VERSION 5.7 ;
  NOWIREEXTENSIONATPIN ON ;
  DIVIDERCHAR "/" ;
  BUSBITCHARS "[]" ;
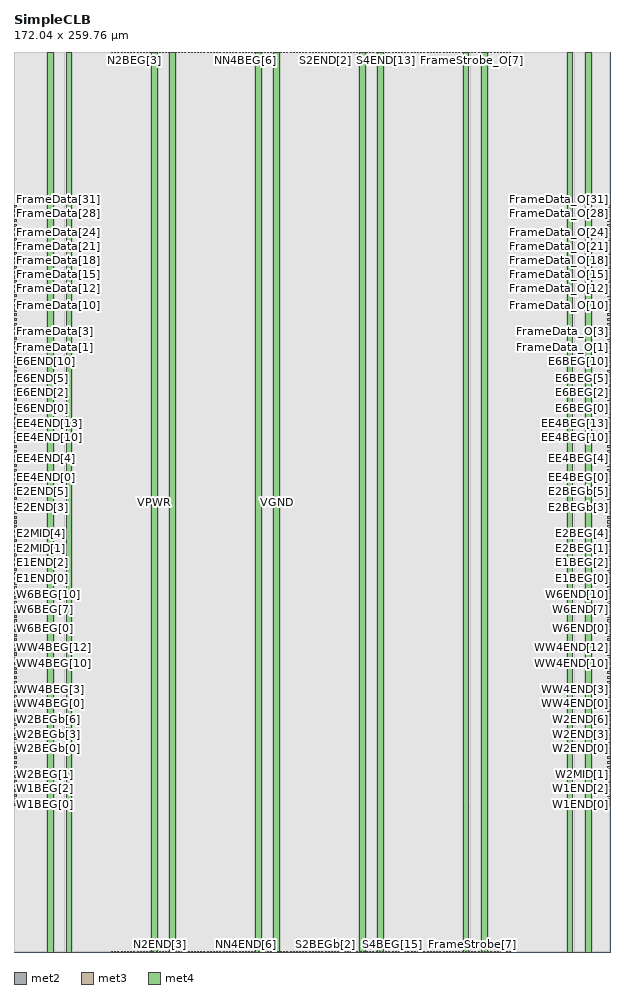
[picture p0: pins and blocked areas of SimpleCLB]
MACRO SimpleCLB
  CLASS BLOCK ;
  FOREIGN SimpleCLB ;
  ORIGIN 0.000 0.000 ;
  SIZE 172.040 BY 259.760 ;
  PIN Ci
    DIRECTION INPUT ;
    USE SIGNAL ;
    ANTENNAGATEAREA 1.485000 ;
    PORT
      LAYER met2 ;
        RECT 75.990 0.000 76.270 0.280 ;
    END
  END Ci
  PIN Co
    DIRECTION OUTPUT ;
    USE SIGNAL ;
    ANTENNADIFFAREA 1.782000 ;
    PORT
      LAYER met2 ;
        RECT 75.990 259.480 76.270 259.760 ;
    END
  END Co
  PIN E1BEG[0]
    DIRECTION OUTPUT ;
    USE SIGNAL ;
    ANTENNADIFFAREA 0.891000 ;
    PORT
      LAYER met3 ;
        RECT 171.440 107.480 172.040 108.080 ;
    END
  END E1BEG[0]
  PIN E1BEG[1]
    DIRECTION OUTPUT ;
    USE SIGNAL ;
    ANTENNADIFFAREA 0.891000 ;
    PORT
      LAYER met3 ;
        RECT 171.440 108.840 172.040 109.440 ;
    END
  END E1BEG[1]
  PIN E1BEG[2]
    DIRECTION OUTPUT ;
    USE SIGNAL ;
    ANTENNADIFFAREA 1.336500 ;
    PORT
      LAYER met3 ;
        RECT 171.440 110.200 172.040 110.800 ;
    END
  END E1BEG[2]
  PIN E1BEG[3]
    DIRECTION OUTPUT ;
    USE SIGNAL ;
    ANTENNADIFFAREA 0.891000 ;
    PORT
      LAYER met3 ;
        RECT 171.440 111.560 172.040 112.160 ;
    END
  END E1BEG[3]
  PIN E1END[0]
    DIRECTION INPUT ;
    USE SIGNAL ;
    ANTENNAGATEAREA 4.176900 ;
    ANTENNADIFFAREA 3.042900 ;
    PORT
      LAYER met3 ;
        RECT 0.000 107.480 0.600 108.080 ;
    END
  END E1END[0]
  PIN E1END[1]
    DIRECTION INPUT ;
    USE SIGNAL ;
    ANTENNAGATEAREA 1.134000 ;
    PORT
      LAYER met3 ;
        RECT 0.000 108.840 0.600 109.440 ;
    END
  END E1END[1]
  PIN E1END[2]
    DIRECTION INPUT ;
    USE SIGNAL ;
    ANTENNAGATEAREA 2.807100 ;
    ANTENNADIFFAREA 1.304100 ;
    PORT
      LAYER met3 ;
        RECT 0.000 110.200 0.600 110.800 ;
    END
  END E1END[2]
  PIN E1END[3]
    DIRECTION INPUT ;
    USE SIGNAL ;
    ANTENNAGATEAREA 0.339000 ;
    PORT
      LAYER met3 ;
        RECT 0.000 111.560 0.600 112.160 ;
    END
  END E1END[3]
  PIN E2BEG[0]
    DIRECTION OUTPUT ;
    USE SIGNAL ;
    ANTENNADIFFAREA 0.891000 ;
    PORT
      LAYER met3 ;
        RECT 171.440 112.920 172.040 113.520 ;
    END
  END E2BEG[0]
  PIN E2BEG[1]
    DIRECTION OUTPUT ;
    USE SIGNAL ;
    ANTENNADIFFAREA 0.891000 ;
    PORT
      LAYER met3 ;
        RECT 171.440 114.280 172.040 114.880 ;
    END
  END E2BEG[1]
  PIN E2BEG[2]
    DIRECTION OUTPUT ;
    USE SIGNAL ;
    ANTENNADIFFAREA 1.336500 ;
    PORT
      LAYER met3 ;
        RECT 171.440 115.640 172.040 116.240 ;
    END
  END E2BEG[2]
  PIN E2BEG[3]
    DIRECTION OUTPUT ;
    USE SIGNAL ;
    ANTENNADIFFAREA 1.336500 ;
    PORT
      LAYER met3 ;
        RECT 171.440 117.000 172.040 117.600 ;
    END
  END E2BEG[3]
  PIN E2BEG[4]
    DIRECTION OUTPUT ;
    USE SIGNAL ;
    ANTENNADIFFAREA 1.782000 ;
    PORT
      LAYER met3 ;
        RECT 171.440 118.360 172.040 118.960 ;
    END
  END E2BEG[4]
  PIN E2BEG[5]
    DIRECTION OUTPUT ;
    USE SIGNAL ;
    ANTENNADIFFAREA 1.336500 ;
    PORT
      LAYER met3 ;
        RECT 171.440 119.720 172.040 120.320 ;
    END
  END E2BEG[5]
  PIN E2BEG[6]
    DIRECTION OUTPUT ;
    USE SIGNAL ;
    ANTENNADIFFAREA 1.782000 ;
    PORT
      LAYER met3 ;
        RECT 171.440 121.080 172.040 121.680 ;
    END
  END E2BEG[6]
  PIN E2BEG[7]
    DIRECTION OUTPUT ;
    USE SIGNAL ;
    ANTENNADIFFAREA 1.336500 ;
    PORT
      LAYER met3 ;
        RECT 171.440 122.440 172.040 123.040 ;
    END
  END E2BEG[7]
  PIN E2BEGb[0]
    DIRECTION OUTPUT ;
    USE SIGNAL ;
    ANTENNADIFFAREA 0.445500 ;
    PORT
      LAYER met3 ;
        RECT 171.440 123.800 172.040 124.400 ;
    END
  END E2BEGb[0]
  PIN E2BEGb[1]
    DIRECTION OUTPUT ;
    USE SIGNAL ;
    ANTENNADIFFAREA 0.445500 ;
    PORT
      LAYER met3 ;
        RECT 171.440 125.160 172.040 125.760 ;
    END
  END E2BEGb[1]
  PIN E2BEGb[2]
    DIRECTION OUTPUT ;
    USE SIGNAL ;
    ANTENNADIFFAREA 0.445500 ;
    PORT
      LAYER met3 ;
        RECT 171.440 126.520 172.040 127.120 ;
    END
  END E2BEGb[2]
  PIN E2BEGb[3]
    DIRECTION OUTPUT ;
    USE SIGNAL ;
    ANTENNADIFFAREA 0.445500 ;
    PORT
      LAYER met3 ;
        RECT 171.440 127.880 172.040 128.480 ;
    END
  END E2BEGb[3]
  PIN E2BEGb[4]
    DIRECTION OUTPUT ;
    USE SIGNAL ;
    ANTENNADIFFAREA 0.445500 ;
    PORT
      LAYER met3 ;
        RECT 171.440 129.240 172.040 129.840 ;
    END
  END E2BEGb[4]
  PIN E2BEGb[5]
    DIRECTION OUTPUT ;
    USE SIGNAL ;
    ANTENNADIFFAREA 0.445500 ;
    PORT
      LAYER met3 ;
        RECT 171.440 130.600 172.040 131.200 ;
    END
  END E2BEGb[5]
  PIN E2BEGb[6]
    DIRECTION OUTPUT ;
    USE SIGNAL ;
    ANTENNADIFFAREA 0.445500 ;
    PORT
      LAYER met3 ;
        RECT 171.440 131.960 172.040 132.560 ;
    END
  END E2BEGb[6]
  PIN E2BEGb[7]
    DIRECTION OUTPUT ;
    USE SIGNAL ;
    ANTENNADIFFAREA 0.445500 ;
    PORT
      LAYER met3 ;
        RECT 171.440 133.320 172.040 133.920 ;
    END
  END E2BEGb[7]
  PIN E2END[0]
    DIRECTION INPUT ;
    USE SIGNAL ;
    ANTENNAGATEAREA 0.537000 ;
    PORT
      LAYER met3 ;
        RECT 0.000 123.800 0.600 124.400 ;
    END
  END E2END[0]
  PIN E2END[1]
    DIRECTION INPUT ;
    USE SIGNAL ;
    ANTENNAGATEAREA 0.537000 ;
    PORT
      LAYER met3 ;
        RECT 0.000 125.160 0.600 125.760 ;
    END
  END E2END[1]
  PIN E2END[2]
    DIRECTION INPUT ;
    USE SIGNAL ;
    ANTENNAGATEAREA 1.014000 ;
    PORT
      LAYER met3 ;
        RECT 0.000 126.520 0.600 127.120 ;
    END
  END E2END[2]
  PIN E2END[3]
    DIRECTION INPUT ;
    USE SIGNAL ;
    ANTENNAGATEAREA 0.981000 ;
    PORT
      LAYER met3 ;
        RECT 0.000 127.880 0.600 128.480 ;
    END
  END E2END[3]
  PIN E2END[4]
    DIRECTION INPUT ;
    USE SIGNAL ;
    ANTENNAGATEAREA 0.663000 ;
    PORT
      LAYER met3 ;
        RECT 0.000 129.240 0.600 129.840 ;
    END
  END E2END[4]
  PIN E2END[5]
    DIRECTION INPUT ;
    USE SIGNAL ;
    ANTENNAGATEAREA 0.822000 ;
    PORT
      LAYER met3 ;
        RECT 0.000 130.600 0.600 131.200 ;
    END
  END E2END[5]
  PIN E2END[6]
    DIRECTION INPUT ;
    USE SIGNAL ;
    ANTENNAGATEAREA 0.822000 ;
    PORT
      LAYER met3 ;
        RECT 0.000 131.960 0.600 132.560 ;
    END
  END E2END[6]
  PIN E2END[7]
    DIRECTION INPUT ;
    USE SIGNAL ;
    ANTENNAGATEAREA 0.663000 ;
    PORT
      LAYER met3 ;
        RECT 0.000 133.320 0.600 133.920 ;
    END
  END E2END[7]
  PIN E2MID[0]
    DIRECTION INPUT ;
    USE SIGNAL ;
    ANTENNAGATEAREA 0.690000 ;
    PORT
      LAYER met3 ;
        RECT 0.000 112.920 0.600 113.520 ;
    END
  END E2MID[0]
  PIN E2MID[1]
    DIRECTION INPUT ;
    USE SIGNAL ;
    ANTENNAGATEAREA 0.799500 ;
    PORT
      LAYER met3 ;
        RECT 0.000 114.280 0.600 114.880 ;
    END
  END E2MID[1]
  PIN E2MID[2]
    DIRECTION INPUT ;
    USE SIGNAL ;
    ANTENNAGATEAREA 0.640500 ;
    PORT
      LAYER met3 ;
        RECT 0.000 115.640 0.600 116.240 ;
    END
  END E2MID[2]
  PIN E2MID[3]
    DIRECTION INPUT ;
    USE SIGNAL ;
    ANTENNAGATEAREA 0.832500 ;
    PORT
      LAYER met3 ;
        RECT 0.000 117.000 0.600 117.600 ;
    END
  END E2MID[3]
  PIN E2MID[4]
    DIRECTION INPUT ;
    USE SIGNAL ;
    ANTENNAGATEAREA 0.937500 ;
    PORT
      LAYER met3 ;
        RECT 0.000 118.360 0.600 118.960 ;
    END
  END E2MID[4]
  PIN E2MID[5]
    DIRECTION INPUT ;
    USE SIGNAL ;
    ANTENNAGATEAREA 0.733500 ;
    PORT
      LAYER met3 ;
        RECT 0.000 119.720 0.600 120.320 ;
    END
  END E2MID[5]
  PIN E2MID[6]
    DIRECTION INPUT ;
    USE SIGNAL ;
    ANTENNAGATEAREA 0.640500 ;
    PORT
      LAYER met3 ;
        RECT 0.000 121.080 0.600 121.680 ;
    END
  END E2MID[6]
  PIN E2MID[7]
    DIRECTION INPUT ;
    USE SIGNAL ;
    ANTENNAGATEAREA 0.766500 ;
    PORT
      LAYER met3 ;
        RECT 0.000 122.440 0.600 123.040 ;
    END
  END E2MID[7]
  PIN E6BEG[0]
    DIRECTION OUTPUT ;
    USE SIGNAL ;
    ANTENNADIFFAREA 0.445500 ;
    PORT
      LAYER met3 ;
        RECT 171.440 156.440 172.040 157.040 ;
    END
  END E6BEG[0]
  PIN E6BEG[10]
    DIRECTION OUTPUT ;
    USE SIGNAL ;
    ANTENNADIFFAREA 1.336500 ;
    PORT
      LAYER met3 ;
        RECT 171.440 170.040 172.040 170.640 ;
    END
  END E6BEG[10]
  PIN E6BEG[11]
    DIRECTION OUTPUT ;
    USE SIGNAL ;
    ANTENNADIFFAREA 1.782000 ;
    PORT
      LAYER met3 ;
        RECT 171.440 171.400 172.040 172.000 ;
    END
  END E6BEG[11]
  PIN E6BEG[1]
    DIRECTION OUTPUT ;
    USE SIGNAL ;
    ANTENNADIFFAREA 0.445500 ;
    PORT
      LAYER met3 ;
        RECT 171.440 157.800 172.040 158.400 ;
    END
  END E6BEG[1]
  PIN E6BEG[2]
    DIRECTION OUTPUT ;
    USE SIGNAL ;
    ANTENNADIFFAREA 0.445500 ;
    PORT
      LAYER met3 ;
        RECT 171.440 159.160 172.040 159.760 ;
    END
  END E6BEG[2]
  PIN E6BEG[3]
    DIRECTION OUTPUT ;
    USE SIGNAL ;
    ANTENNADIFFAREA 0.445500 ;
    PORT
      LAYER met3 ;
        RECT 171.440 160.520 172.040 161.120 ;
    END
  END E6BEG[3]
  PIN E6BEG[4]
    DIRECTION OUTPUT ;
    USE SIGNAL ;
    ANTENNADIFFAREA 0.445500 ;
    PORT
      LAYER met3 ;
        RECT 171.440 161.880 172.040 162.480 ;
    END
  END E6BEG[4]
  PIN E6BEG[5]
    DIRECTION OUTPUT ;
    USE SIGNAL ;
    ANTENNADIFFAREA 0.445500 ;
    PORT
      LAYER met3 ;
        RECT 171.440 163.240 172.040 163.840 ;
    END
  END E6BEG[5]
  PIN E6BEG[6]
    DIRECTION OUTPUT ;
    USE SIGNAL ;
    ANTENNADIFFAREA 0.445500 ;
    PORT
      LAYER met3 ;
        RECT 171.440 164.600 172.040 165.200 ;
    END
  END E6BEG[6]
  PIN E6BEG[7]
    DIRECTION OUTPUT ;
    USE SIGNAL ;
    ANTENNADIFFAREA 0.445500 ;
    PORT
      LAYER met3 ;
        RECT 171.440 165.960 172.040 166.560 ;
    END
  END E6BEG[7]
  PIN E6BEG[8]
    DIRECTION OUTPUT ;
    USE SIGNAL ;
    ANTENNADIFFAREA 0.445500 ;
    PORT
      LAYER met3 ;
        RECT 171.440 167.320 172.040 167.920 ;
    END
  END E6BEG[8]
  PIN E6BEG[9]
    DIRECTION OUTPUT ;
    USE SIGNAL ;
    ANTENNADIFFAREA 0.445500 ;
    PORT
      LAYER met3 ;
        RECT 171.440 168.680 172.040 169.280 ;
    END
  END E6BEG[9]
  PIN E6END[0]
    DIRECTION INPUT ;
    USE SIGNAL ;
    ANTENNAGATEAREA 0.845700 ;
    ANTENNADIFFAREA 0.434700 ;
    PORT
      LAYER met3 ;
        RECT 0.000 156.440 0.600 157.040 ;
    END
  END E6END[0]
  PIN E6END[10]
    DIRECTION INPUT ;
    USE SIGNAL ;
    ANTENNAGATEAREA 0.196500 ;
    PORT
      LAYER met3 ;
        RECT 0.000 170.040 0.600 170.640 ;
    END
  END E6END[10]
  PIN E6END[11]
    DIRECTION INPUT ;
    USE SIGNAL ;
    ANTENNAGATEAREA 0.196500 ;
    PORT
      LAYER met3 ;
        RECT 0.000 171.400 0.600 172.000 ;
    END
  END E6END[11]
  PIN E6END[1]
    DIRECTION INPUT ;
    USE SIGNAL ;
    ANTENNAGATEAREA 0.465000 ;
    PORT
      LAYER met3 ;
        RECT 0.000 157.800 0.600 158.400 ;
    END
  END E6END[1]
  PIN E6END[2]
    DIRECTION INPUT ;
    USE SIGNAL ;
    ANTENNAGATEAREA 0.196500 ;
    PORT
      LAYER met3 ;
        RECT 0.000 159.160 0.600 159.760 ;
    END
  END E6END[2]
  PIN E6END[3]
    DIRECTION INPUT ;
    USE SIGNAL ;
    ANTENNAGATEAREA 0.196500 ;
    PORT
      LAYER met3 ;
        RECT 0.000 160.520 0.600 161.120 ;
    END
  END E6END[3]
  PIN E6END[4]
    DIRECTION INPUT ;
    USE SIGNAL ;
    ANTENNAGATEAREA 0.631200 ;
    ANTENNADIFFAREA 0.434700 ;
    PORT
      LAYER met3 ;
        RECT 0.000 161.880 0.600 162.480 ;
    END
  END E6END[4]
  PIN E6END[5]
    DIRECTION INPUT ;
    USE SIGNAL ;
    ANTENNAGATEAREA 0.631200 ;
    ANTENNADIFFAREA 0.434700 ;
    PORT
      LAYER met3 ;
        RECT 0.000 163.240 0.600 163.840 ;
    END
  END E6END[5]
  PIN E6END[6]
    DIRECTION INPUT ;
    USE SIGNAL ;
    ANTENNAGATEAREA 0.196500 ;
    PORT
      LAYER met3 ;
        RECT 0.000 164.600 0.600 165.200 ;
    END
  END E6END[6]
  PIN E6END[7]
    DIRECTION INPUT ;
    USE SIGNAL ;
    ANTENNAGATEAREA 1.065900 ;
    ANTENNADIFFAREA 0.869400 ;
    PORT
      LAYER met3 ;
        RECT 0.000 165.960 0.600 166.560 ;
    END
  END E6END[7]
  PIN E6END[8]
    DIRECTION INPUT ;
    USE SIGNAL ;
    ANTENNAGATEAREA 0.631200 ;
    ANTENNADIFFAREA 0.434700 ;
    PORT
      LAYER met3 ;
        RECT 0.000 167.320 0.600 167.920 ;
    END
  END E6END[8]
  PIN E6END[9]
    DIRECTION INPUT ;
    USE SIGNAL ;
    ANTENNAGATEAREA 0.631200 ;
    ANTENNADIFFAREA 0.434700 ;
    PORT
      LAYER met3 ;
        RECT 0.000 168.680 0.600 169.280 ;
    END
  END E6END[9]
  PIN EE4BEG[0]
    DIRECTION OUTPUT ;
    USE SIGNAL ;
    ANTENNADIFFAREA 0.445500 ;
    PORT
      LAYER met3 ;
        RECT 171.440 134.680 172.040 135.280 ;
    END
  END EE4BEG[0]
  PIN EE4BEG[10]
    DIRECTION OUTPUT ;
    USE SIGNAL ;
    ANTENNADIFFAREA 0.445500 ;
    PORT
      LAYER met3 ;
        RECT 171.440 148.280 172.040 148.880 ;
    END
  END EE4BEG[10]
  PIN EE4BEG[11]
    DIRECTION OUTPUT ;
    USE SIGNAL ;
    ANTENNADIFFAREA 0.445500 ;
    PORT
      LAYER met3 ;
        RECT 171.440 149.640 172.040 150.240 ;
    END
  END EE4BEG[11]
  PIN EE4BEG[12]
    DIRECTION OUTPUT ;
    USE SIGNAL ;
    ANTENNADIFFAREA 1.782000 ;
    PORT
      LAYER met3 ;
        RECT 171.440 151.000 172.040 151.600 ;
    END
  END EE4BEG[12]
  PIN EE4BEG[13]
    DIRECTION OUTPUT ;
    USE SIGNAL ;
    ANTENNADIFFAREA 1.782000 ;
    PORT
      LAYER met3 ;
        RECT 171.440 152.360 172.040 152.960 ;
    END
  END EE4BEG[13]
  PIN EE4BEG[14]
    DIRECTION OUTPUT ;
    USE SIGNAL ;
    ANTENNADIFFAREA 1.336500 ;
    PORT
      LAYER met3 ;
        RECT 171.440 153.720 172.040 154.320 ;
    END
  END EE4BEG[14]
  PIN EE4BEG[15]
    DIRECTION OUTPUT ;
    USE SIGNAL ;
    ANTENNADIFFAREA 0.795200 ;
    PORT
      LAYER met3 ;
        RECT 171.440 155.080 172.040 155.680 ;
    END
  END EE4BEG[15]
  PIN EE4BEG[1]
    DIRECTION OUTPUT ;
    USE SIGNAL ;
    ANTENNADIFFAREA 0.445500 ;
    PORT
      LAYER met3 ;
        RECT 171.440 136.040 172.040 136.640 ;
    END
  END EE4BEG[1]
  PIN EE4BEG[2]
    DIRECTION OUTPUT ;
    USE SIGNAL ;
    ANTENNADIFFAREA 0.445500 ;
    PORT
      LAYER met3 ;
        RECT 171.440 137.400 172.040 138.000 ;
    END
  END EE4BEG[2]
  PIN EE4BEG[3]
    DIRECTION OUTPUT ;
    USE SIGNAL ;
    ANTENNADIFFAREA 0.445500 ;
    PORT
      LAYER met3 ;
        RECT 171.440 138.760 172.040 139.360 ;
    END
  END EE4BEG[3]
  PIN EE4BEG[4]
    DIRECTION OUTPUT ;
    USE SIGNAL ;
    ANTENNADIFFAREA 0.445500 ;
    PORT
      LAYER met3 ;
        RECT 171.440 140.120 172.040 140.720 ;
    END
  END EE4BEG[4]
  PIN EE4BEG[5]
    DIRECTION OUTPUT ;
    USE SIGNAL ;
    ANTENNADIFFAREA 0.445500 ;
    PORT
      LAYER met3 ;
        RECT 171.440 141.480 172.040 142.080 ;
    END
  END EE4BEG[5]
  PIN EE4BEG[6]
    DIRECTION OUTPUT ;
    USE SIGNAL ;
    ANTENNADIFFAREA 0.445500 ;
    PORT
      LAYER met3 ;
        RECT 171.440 142.840 172.040 143.440 ;
    END
  END EE4BEG[6]
  PIN EE4BEG[7]
    DIRECTION OUTPUT ;
    USE SIGNAL ;
    ANTENNADIFFAREA 0.445500 ;
    PORT
      LAYER met3 ;
        RECT 171.440 144.200 172.040 144.800 ;
    END
  END EE4BEG[7]
  PIN EE4BEG[8]
    DIRECTION OUTPUT ;
    USE SIGNAL ;
    ANTENNADIFFAREA 0.445500 ;
    PORT
      LAYER met3 ;
        RECT 171.440 145.560 172.040 146.160 ;
    END
  END EE4BEG[8]
  PIN EE4BEG[9]
    DIRECTION OUTPUT ;
    USE SIGNAL ;
    ANTENNADIFFAREA 0.445500 ;
    PORT
      LAYER met3 ;
        RECT 171.440 146.920 172.040 147.520 ;
    END
  END EE4BEG[9]
  PIN EE4END[0]
    DIRECTION INPUT ;
    USE SIGNAL ;
    ANTENNAGATEAREA 1.715100 ;
    ANTENNADIFFAREA 1.304100 ;
    PORT
      LAYER met3 ;
        RECT 0.000 134.680 0.600 135.280 ;
    END
  END EE4END[0]
  PIN EE4END[10]
    DIRECTION INPUT ;
    USE SIGNAL ;
    ANTENNAGATEAREA 0.631200 ;
    ANTENNADIFFAREA 0.434700 ;
    PORT
      LAYER met3 ;
        RECT 0.000 148.280 0.600 148.880 ;
    END
  END EE4END[10]
  PIN EE4END[11]
    DIRECTION INPUT ;
    USE SIGNAL ;
    ANTENNAGATEAREA 1.065900 ;
    ANTENNADIFFAREA 0.869400 ;
    PORT
      LAYER met3 ;
        RECT 0.000 149.640 0.600 150.240 ;
    END
  END EE4END[11]
  PIN EE4END[12]
    DIRECTION INPUT ;
    USE SIGNAL ;
    ANTENNAGATEAREA 0.631200 ;
    ANTENNADIFFAREA 0.434700 ;
    PORT
      LAYER met3 ;
        RECT 0.000 151.000 0.600 151.600 ;
    END
  END EE4END[12]
  PIN EE4END[13]
    DIRECTION INPUT ;
    USE SIGNAL ;
    ANTENNAGATEAREA 0.196500 ;
    PORT
      LAYER met3 ;
        RECT 0.000 152.360 0.600 152.960 ;
    END
  END EE4END[13]
  PIN EE4END[14]
    DIRECTION INPUT ;
    USE SIGNAL ;
    ANTENNAGATEAREA 0.631200 ;
    ANTENNADIFFAREA 0.434700 ;
    PORT
      LAYER met3 ;
        RECT 0.000 153.720 0.600 154.320 ;
    END
  END EE4END[14]
  PIN EE4END[15]
    DIRECTION INPUT ;
    USE SIGNAL ;
    ANTENNAGATEAREA 0.631200 ;
    ANTENNADIFFAREA 0.434700 ;
    PORT
      LAYER met3 ;
        RECT 0.000 155.080 0.600 155.680 ;
    END
  END EE4END[15]
  PIN EE4END[1]
    DIRECTION INPUT ;
    USE SIGNAL ;
    ANTENNAGATEAREA 0.444000 ;
    PORT
      LAYER met3 ;
        RECT 0.000 136.040 0.600 136.640 ;
    END
  END EE4END[1]
  PIN EE4END[2]
    DIRECTION INPUT ;
    USE SIGNAL ;
    ANTENNAGATEAREA 0.845700 ;
    ANTENNADIFFAREA 0.434700 ;
    PORT
      LAYER met3 ;
        RECT 0.000 137.400 0.600 138.000 ;
    END
  END EE4END[2]
  PIN EE4END[3]
    DIRECTION INPUT ;
    USE SIGNAL ;
    ANTENNAGATEAREA 0.878700 ;
    ANTENNADIFFAREA 0.434700 ;
    PORT
      LAYER met3 ;
        RECT 0.000 138.760 0.600 139.360 ;
    END
  END EE4END[3]
  PIN EE4END[4]
    DIRECTION INPUT ;
    USE SIGNAL ;
    ANTENNAGATEAREA 0.631200 ;
    ANTENNADIFFAREA 0.434700 ;
    PORT
      LAYER met3 ;
        RECT 0.000 140.120 0.600 140.720 ;
    END
  END EE4END[4]
  PIN EE4END[5]
    DIRECTION INPUT ;
    USE SIGNAL ;
    ANTENNAGATEAREA 0.631200 ;
    ANTENNADIFFAREA 0.434700 ;
    PORT
      LAYER met3 ;
        RECT 0.000 141.480 0.600 142.080 ;
    END
  END EE4END[5]
  PIN EE4END[6]
    DIRECTION INPUT ;
    USE SIGNAL ;
    ANTENNAGATEAREA 0.196500 ;
    PORT
      LAYER met3 ;
        RECT 0.000 142.840 0.600 143.440 ;
    END
  END EE4END[6]
  PIN EE4END[7]
    DIRECTION INPUT ;
    USE SIGNAL ;
    ANTENNAGATEAREA 0.631200 ;
    ANTENNADIFFAREA 0.434700 ;
    PORT
      LAYER met3 ;
        RECT 0.000 144.200 0.600 144.800 ;
    END
  END EE4END[7]
  PIN EE4END[8]
    DIRECTION INPUT ;
    USE SIGNAL ;
    ANTENNAGATEAREA 0.196500 ;
    PORT
      LAYER met3 ;
        RECT 0.000 145.560 0.600 146.160 ;
    END
  END EE4END[8]
  PIN EE4END[9]
    DIRECTION INPUT ;
    USE SIGNAL ;
    ANTENNAGATEAREA 1.065900 ;
    ANTENNADIFFAREA 0.869400 ;
    PORT
      LAYER met3 ;
        RECT 0.000 146.920 0.600 147.520 ;
    END
  END EE4END[9]
  PIN FrameData[0]
    DIRECTION INPUT ;
    USE SIGNAL ;
    ANTENNAGATEAREA 1.329900 ;
    ANTENNADIFFAREA 0.869400 ;
    PORT
      LAYER met3 ;
        RECT 0.000 172.760 0.600 173.360 ;
    END
  END FrameData[0]
  PIN FrameData[10]
    DIRECTION INPUT ;
    USE SIGNAL ;
    ANTENNAGATEAREA 0.444000 ;
    PORT
      LAYER met3 ;
        RECT 0.000 186.360 0.600 186.960 ;
    END
  END FrameData[10]
  PIN FrameData[11]
    DIRECTION INPUT ;
    USE SIGNAL ;
    ANTENNAGATEAREA 0.444000 ;
    PORT
      LAYER met3 ;
        RECT 0.000 187.720 0.600 188.320 ;
    END
  END FrameData[11]
  PIN FrameData[12]
    DIRECTION INPUT ;
    USE SIGNAL ;
    ANTENNAGATEAREA 0.406500 ;
    PORT
      LAYER met3 ;
        RECT 0.000 189.080 0.600 189.680 ;
    END
  END FrameData[12]
  PIN FrameData[13]
    DIRECTION INPUT ;
    USE SIGNAL ;
    ANTENNAGATEAREA 0.426000 ;
    PORT
      LAYER met3 ;
        RECT 0.000 190.440 0.600 191.040 ;
    END
  END FrameData[13]
  PIN FrameData[14]
    DIRECTION INPUT ;
    USE SIGNAL ;
    ANTENNAGATEAREA 1.275900 ;
    ANTENNADIFFAREA 0.869400 ;
    PORT
      LAYER met3 ;
        RECT 0.000 191.800 0.600 192.400 ;
    END
  END FrameData[14]
  PIN FrameData[15]
    DIRECTION INPUT ;
    USE SIGNAL ;
    ANTENNAGATEAREA 0.406500 ;
    PORT
      LAYER met3 ;
        RECT 0.000 193.160 0.600 193.760 ;
    END
  END FrameData[15]
  PIN FrameData[16]
    DIRECTION INPUT ;
    USE SIGNAL ;
    ANTENNAGATEAREA 1.275900 ;
    ANTENNADIFFAREA 0.869400 ;
    PORT
      LAYER met3 ;
        RECT 0.000 194.520 0.600 195.120 ;
    END
  END FrameData[16]
  PIN FrameData[17]
    DIRECTION INPUT ;
    USE SIGNAL ;
    ANTENNAGATEAREA 1.275900 ;
    ANTENNADIFFAREA 0.869400 ;
    PORT
      LAYER met3 ;
        RECT 0.000 195.880 0.600 196.480 ;
    END
  END FrameData[17]
  PIN FrameData[18]
    DIRECTION INPUT ;
    USE SIGNAL ;
    ANTENNAGATEAREA 1.275900 ;
    ANTENNADIFFAREA 0.869400 ;
    PORT
      LAYER met3 ;
        RECT 0.000 197.240 0.600 197.840 ;
    END
  END FrameData[18]
  PIN FrameData[19]
    DIRECTION INPUT ;
    USE SIGNAL ;
    ANTENNAGATEAREA 0.406500 ;
    PORT
      LAYER met3 ;
        RECT 0.000 198.600 0.600 199.200 ;
    END
  END FrameData[19]
  PIN FrameData[1]
    DIRECTION INPUT ;
    USE SIGNAL ;
    ANTENNAGATEAREA 0.860700 ;
    ANTENNADIFFAREA 0.434700 ;
    PORT
      LAYER met3 ;
        RECT 0.000 174.120 0.600 174.720 ;
    END
  END FrameData[1]
  PIN FrameData[20]
    DIRECTION INPUT ;
    USE SIGNAL ;
    ANTENNAGATEAREA 0.159000 ;
    PORT
      LAYER met3 ;
        RECT 0.000 199.960 0.600 200.560 ;
    END
  END FrameData[20]
  PIN FrameData[21]
    DIRECTION INPUT ;
    USE SIGNAL ;
    ANTENNAGATEAREA 0.593700 ;
    ANTENNADIFFAREA 0.434700 ;
    PORT
      LAYER met3 ;
        RECT 0.000 201.320 0.600 201.920 ;
    END
  END FrameData[21]
  PIN FrameData[22]
    DIRECTION INPUT ;
    USE SIGNAL ;
    ANTENNAGATEAREA 0.406500 ;
    PORT
      LAYER met3 ;
        RECT 0.000 202.680 0.600 203.280 ;
    END
  END FrameData[22]
  PIN FrameData[23]
    DIRECTION INPUT ;
    USE SIGNAL ;
    ANTENNAGATEAREA 0.406500 ;
    PORT
      LAYER met3 ;
        RECT 0.000 204.040 0.600 204.640 ;
    END
  END FrameData[23]
  PIN FrameData[24]
    DIRECTION INPUT ;
    USE SIGNAL ;
    ANTENNAGATEAREA 0.585000 ;
    PORT
      LAYER met3 ;
        RECT 0.000 205.400 0.600 206.000 ;
    END
  END FrameData[24]
  PIN FrameData[25]
    DIRECTION INPUT ;
    USE SIGNAL ;
    ANTENNAGATEAREA 0.406500 ;
    PORT
      LAYER met3 ;
        RECT 0.000 206.760 0.600 207.360 ;
    END
  END FrameData[25]
  PIN FrameData[26]
    DIRECTION INPUT ;
    USE SIGNAL ;
    ANTENNAGATEAREA 0.372000 ;
    PORT
      LAYER met3 ;
        RECT 0.000 208.120 0.600 208.720 ;
    END
  END FrameData[26]
  PIN FrameData[27]
    DIRECTION INPUT ;
    USE SIGNAL ;
    ANTENNAGATEAREA 0.372000 ;
    PORT
      LAYER met3 ;
        RECT 0.000 209.480 0.600 210.080 ;
    END
  END FrameData[27]
  PIN FrameData[28]
    DIRECTION INPUT ;
    USE SIGNAL ;
    ANTENNAGATEAREA 0.406500 ;
    PORT
      LAYER met3 ;
        RECT 0.000 210.840 0.600 211.440 ;
    END
  END FrameData[28]
  PIN FrameData[29]
    DIRECTION INPUT ;
    USE SIGNAL ;
    ANTENNAGATEAREA 0.213000 ;
    PORT
      LAYER met3 ;
        RECT 0.000 212.200 0.600 212.800 ;
    END
  END FrameData[29]
  PIN FrameData[2]
    DIRECTION INPUT ;
    USE SIGNAL ;
    ANTENNAGATEAREA 1.275900 ;
    ANTENNADIFFAREA 0.869400 ;
    PORT
      LAYER met3 ;
        RECT 0.000 175.480 0.600 176.080 ;
    END
  END FrameData[2]
  PIN FrameData[30]
    DIRECTION INPUT ;
    USE SIGNAL ;
    ANTENNAGATEAREA 0.406500 ;
    PORT
      LAYER met3 ;
        RECT 0.000 213.560 0.600 214.160 ;
    END
  END FrameData[30]
  PIN FrameData[31]
    DIRECTION INPUT ;
    USE SIGNAL ;
    ANTENNAGATEAREA 0.460500 ;
    PORT
      LAYER met3 ;
        RECT 0.000 214.920 0.600 215.520 ;
    END
  END FrameData[31]
  PIN FrameData[3]
    DIRECTION INPUT ;
    USE SIGNAL ;
    ANTENNAGATEAREA 1.275900 ;
    ANTENNADIFFAREA 0.869400 ;
    PORT
      LAYER met3 ;
        RECT 0.000 176.840 0.600 177.440 ;
    END
  END FrameData[3]
  PIN FrameData[4]
    DIRECTION INPUT ;
    USE SIGNAL ;
    ANTENNAGATEAREA 1.295400 ;
    ANTENNADIFFAREA 0.869400 ;
    PORT
      LAYER met3 ;
        RECT 0.000 178.200 0.600 178.800 ;
    END
  END FrameData[4]
  PIN FrameData[5]
    DIRECTION INPUT ;
    USE SIGNAL ;
    ANTENNAGATEAREA 0.426000 ;
    PORT
      LAYER met3 ;
        RECT 0.000 179.560 0.600 180.160 ;
    END
  END FrameData[5]
  PIN FrameData[6]
    DIRECTION INPUT ;
    USE SIGNAL ;
    ANTENNAGATEAREA 0.406500 ;
    PORT
      LAYER met3 ;
        RECT 0.000 180.920 0.600 181.520 ;
    END
  END FrameData[6]
  PIN FrameData[7]
    DIRECTION INPUT ;
    USE SIGNAL ;
    ANTENNAGATEAREA 0.406500 ;
    PORT
      LAYER met3 ;
        RECT 0.000 182.280 0.600 182.880 ;
    END
  END FrameData[7]
  PIN FrameData[8]
    DIRECTION INPUT ;
    USE SIGNAL ;
    ANTENNAGATEAREA 0.406500 ;
    PORT
      LAYER met3 ;
        RECT 0.000 183.640 0.600 184.240 ;
    END
  END FrameData[8]
  PIN FrameData[9]
    DIRECTION INPUT ;
    USE SIGNAL ;
    ANTENNAGATEAREA 1.275900 ;
    ANTENNADIFFAREA 0.869400 ;
    PORT
      LAYER met3 ;
        RECT 0.000 185.000 0.600 185.600 ;
    END
  END FrameData[9]
  PIN FrameData_O[0]
    DIRECTION OUTPUT ;
    USE SIGNAL ;
    ANTENNADIFFAREA 0.445500 ;
    PORT
      LAYER met3 ;
        RECT 171.440 172.760 172.040 173.360 ;
    END
  END FrameData_O[0]
  PIN FrameData_O[10]
    DIRECTION OUTPUT ;
    USE SIGNAL ;
    ANTENNADIFFAREA 0.445500 ;
    PORT
      LAYER met3 ;
        RECT 171.440 186.360 172.040 186.960 ;
    END
  END FrameData_O[10]
  PIN FrameData_O[11]
    DIRECTION OUTPUT ;
    USE SIGNAL ;
    ANTENNADIFFAREA 0.445500 ;
    PORT
      LAYER met3 ;
        RECT 171.440 187.720 172.040 188.320 ;
    END
  END FrameData_O[11]
  PIN FrameData_O[12]
    DIRECTION OUTPUT ;
    USE SIGNAL ;
    ANTENNADIFFAREA 0.445500 ;
    PORT
      LAYER met3 ;
        RECT 171.440 189.080 172.040 189.680 ;
    END
  END FrameData_O[12]
  PIN FrameData_O[13]
    DIRECTION OUTPUT ;
    USE SIGNAL ;
    ANTENNADIFFAREA 0.445500 ;
    PORT
      LAYER met3 ;
        RECT 171.440 190.440 172.040 191.040 ;
    END
  END FrameData_O[13]
  PIN FrameData_O[14]
    DIRECTION OUTPUT ;
    USE SIGNAL ;
    ANTENNADIFFAREA 0.445500 ;
    PORT
      LAYER met3 ;
        RECT 171.440 191.800 172.040 192.400 ;
    END
  END FrameData_O[14]
  PIN FrameData_O[15]
    DIRECTION OUTPUT ;
    USE SIGNAL ;
    ANTENNADIFFAREA 0.445500 ;
    PORT
      LAYER met3 ;
        RECT 171.440 193.160 172.040 193.760 ;
    END
  END FrameData_O[15]
  PIN FrameData_O[16]
    DIRECTION OUTPUT ;
    USE SIGNAL ;
    ANTENNADIFFAREA 0.445500 ;
    PORT
      LAYER met3 ;
        RECT 171.440 194.520 172.040 195.120 ;
    END
  END FrameData_O[16]
  PIN FrameData_O[17]
    DIRECTION OUTPUT ;
    USE SIGNAL ;
    ANTENNADIFFAREA 0.445500 ;
    PORT
      LAYER met3 ;
        RECT 171.440 195.880 172.040 196.480 ;
    END
  END FrameData_O[17]
  PIN FrameData_O[18]
    DIRECTION OUTPUT ;
    USE SIGNAL ;
    ANTENNADIFFAREA 0.445500 ;
    PORT
      LAYER met3 ;
        RECT 171.440 197.240 172.040 197.840 ;
    END
  END FrameData_O[18]
  PIN FrameData_O[19]
    DIRECTION OUTPUT ;
    USE SIGNAL ;
    ANTENNADIFFAREA 0.445500 ;
    PORT
      LAYER met3 ;
        RECT 171.440 198.600 172.040 199.200 ;
    END
  END FrameData_O[19]
  PIN FrameData_O[1]
    DIRECTION OUTPUT ;
    USE SIGNAL ;
    ANTENNADIFFAREA 0.445500 ;
    PORT
      LAYER met3 ;
        RECT 171.440 174.120 172.040 174.720 ;
    END
  END FrameData_O[1]
  PIN FrameData_O[20]
    DIRECTION OUTPUT ;
    USE SIGNAL ;
    ANTENNADIFFAREA 0.445500 ;
    PORT
      LAYER met3 ;
        RECT 171.440 199.960 172.040 200.560 ;
    END
  END FrameData_O[20]
  PIN FrameData_O[21]
    DIRECTION OUTPUT ;
    USE SIGNAL ;
    ANTENNADIFFAREA 0.445500 ;
    PORT
      LAYER met3 ;
        RECT 171.440 201.320 172.040 201.920 ;
    END
  END FrameData_O[21]
  PIN FrameData_O[22]
    DIRECTION OUTPUT ;
    USE SIGNAL ;
    ANTENNADIFFAREA 0.445500 ;
    PORT
      LAYER met3 ;
        RECT 171.440 202.680 172.040 203.280 ;
    END
  END FrameData_O[22]
  PIN FrameData_O[23]
    DIRECTION OUTPUT ;
    USE SIGNAL ;
    ANTENNADIFFAREA 0.445500 ;
    PORT
      LAYER met3 ;
        RECT 171.440 204.040 172.040 204.640 ;
    END
  END FrameData_O[23]
  PIN FrameData_O[24]
    DIRECTION OUTPUT ;
    USE SIGNAL ;
    ANTENNADIFFAREA 0.445500 ;
    PORT
      LAYER met3 ;
        RECT 171.440 205.400 172.040 206.000 ;
    END
  END FrameData_O[24]
  PIN FrameData_O[25]
    DIRECTION OUTPUT ;
    USE SIGNAL ;
    ANTENNADIFFAREA 0.445500 ;
    PORT
      LAYER met3 ;
        RECT 171.440 206.760 172.040 207.360 ;
    END
  END FrameData_O[25]
  PIN FrameData_O[26]
    DIRECTION OUTPUT ;
    USE SIGNAL ;
    ANTENNADIFFAREA 0.445500 ;
    PORT
      LAYER met3 ;
        RECT 171.440 208.120 172.040 208.720 ;
    END
  END FrameData_O[26]
  PIN FrameData_O[27]
    DIRECTION OUTPUT ;
    USE SIGNAL ;
    ANTENNADIFFAREA 0.445500 ;
    PORT
      LAYER met3 ;
        RECT 171.440 209.480 172.040 210.080 ;
    END
  END FrameData_O[27]
  PIN FrameData_O[28]
    DIRECTION OUTPUT ;
    USE SIGNAL ;
    ANTENNADIFFAREA 0.445500 ;
    PORT
      LAYER met3 ;
        RECT 171.440 210.840 172.040 211.440 ;
    END
  END FrameData_O[28]
  PIN FrameData_O[29]
    DIRECTION OUTPUT ;
    USE SIGNAL ;
    ANTENNADIFFAREA 0.445500 ;
    PORT
      LAYER met3 ;
        RECT 171.440 212.200 172.040 212.800 ;
    END
  END FrameData_O[29]
  PIN FrameData_O[2]
    DIRECTION OUTPUT ;
    USE SIGNAL ;
    ANTENNADIFFAREA 0.445500 ;
    PORT
      LAYER met3 ;
        RECT 171.440 175.480 172.040 176.080 ;
    END
  END FrameData_O[2]
  PIN FrameData_O[30]
    DIRECTION OUTPUT ;
    USE SIGNAL ;
    ANTENNADIFFAREA 0.445500 ;
    PORT
      LAYER met3 ;
        RECT 171.440 213.560 172.040 214.160 ;
    END
  END FrameData_O[30]
  PIN FrameData_O[31]
    DIRECTION OUTPUT ;
    USE SIGNAL ;
    ANTENNADIFFAREA 0.445500 ;
    PORT
      LAYER met3 ;
        RECT 171.440 214.920 172.040 215.520 ;
    END
  END FrameData_O[31]
  PIN FrameData_O[3]
    DIRECTION OUTPUT ;
    USE SIGNAL ;
    ANTENNADIFFAREA 0.445500 ;
    PORT
      LAYER met3 ;
        RECT 171.440 176.840 172.040 177.440 ;
    END
  END FrameData_O[3]
  PIN FrameData_O[4]
    DIRECTION OUTPUT ;
    USE SIGNAL ;
    ANTENNADIFFAREA 0.445500 ;
    PORT
      LAYER met3 ;
        RECT 171.440 178.200 172.040 178.800 ;
    END
  END FrameData_O[4]
  PIN FrameData_O[5]
    DIRECTION OUTPUT ;
    USE SIGNAL ;
    ANTENNADIFFAREA 0.445500 ;
    PORT
      LAYER met3 ;
        RECT 171.440 179.560 172.040 180.160 ;
    END
  END FrameData_O[5]
  PIN FrameData_O[6]
    DIRECTION OUTPUT ;
    USE SIGNAL ;
    ANTENNADIFFAREA 0.445500 ;
    PORT
      LAYER met3 ;
        RECT 171.440 180.920 172.040 181.520 ;
    END
  END FrameData_O[6]
  PIN FrameData_O[7]
    DIRECTION OUTPUT ;
    USE SIGNAL ;
    ANTENNADIFFAREA 0.445500 ;
    PORT
      LAYER met3 ;
        RECT 171.440 182.280 172.040 182.880 ;
    END
  END FrameData_O[7]
  PIN FrameData_O[8]
    DIRECTION OUTPUT ;
    USE SIGNAL ;
    ANTENNADIFFAREA 0.445500 ;
    PORT
      LAYER met3 ;
        RECT 171.440 183.640 172.040 184.240 ;
    END
  END FrameData_O[8]
  PIN FrameData_O[9]
    DIRECTION OUTPUT ;
    USE SIGNAL ;
    ANTENNADIFFAREA 0.445500 ;
    PORT
      LAYER met3 ;
        RECT 171.440 185.000 172.040 185.600 ;
    END
  END FrameData_O[9]
  PIN FrameStrobe[0]
    DIRECTION INPUT ;
    USE SIGNAL ;
    ANTENNAGATEAREA 0.213000 ;
    PORT
      LAYER met2 ;
        RECT 125.670 0.000 125.950 0.280 ;
    END
  END FrameStrobe[0]
  PIN FrameStrobe[10]
    DIRECTION INPUT ;
    USE SIGNAL ;
    ANTENNAGATEAREA 0.247500 ;
    PORT
      LAYER met2 ;
        RECT 134.870 0.000 135.150 0.280 ;
    END
  END FrameStrobe[10]
  PIN FrameStrobe[11]
    DIRECTION INPUT ;
    USE SIGNAL ;
    ANTENNAGATEAREA 0.682200 ;
    ANTENNADIFFAREA 0.434700 ;
    PORT
      LAYER met2 ;
        RECT 135.790 0.000 136.070 0.280 ;
    END
  END FrameStrobe[11]
  PIN FrameStrobe[12]
    DIRECTION INPUT ;
    USE SIGNAL ;
    ANTENNAGATEAREA 0.639000 ;
    PORT
      LAYER met2 ;
        RECT 136.710 0.000 136.990 0.280 ;
    END
  END FrameStrobe[12]
  PIN FrameStrobe[13]
    DIRECTION INPUT ;
    USE SIGNAL ;
    ANTENNAGATEAREA 0.213000 ;
    PORT
      LAYER met2 ;
        RECT 137.630 0.000 137.910 0.280 ;
    END
  END FrameStrobe[13]
  PIN FrameStrobe[14]
    DIRECTION INPUT ;
    USE SIGNAL ;
    ANTENNAGATEAREA 0.593700 ;
    ANTENNADIFFAREA 0.434700 ;
    PORT
      LAYER met2 ;
        RECT 138.550 0.000 138.830 0.280 ;
    END
  END FrameStrobe[14]
  PIN FrameStrobe[15]
    DIRECTION INPUT ;
    USE SIGNAL ;
    ANTENNAGATEAREA 0.647700 ;
    ANTENNADIFFAREA 0.434700 ;
    PORT
      LAYER met2 ;
        RECT 139.470 0.000 139.750 0.280 ;
    END
  END FrameStrobe[15]
  PIN FrameStrobe[16]
    DIRECTION INPUT ;
    USE SIGNAL ;
    ANTENNAGATEAREA 0.560700 ;
    ANTENNADIFFAREA 0.434700 ;
    PORT
      LAYER met2 ;
        RECT 140.390 0.000 140.670 0.280 ;
    END
  END FrameStrobe[16]
  PIN FrameStrobe[17]
    DIRECTION INPUT ;
    USE SIGNAL ;
    ANTENNAGATEAREA 0.426000 ;
    PORT
      LAYER met2 ;
        RECT 141.310 0.000 141.590 0.280 ;
    END
  END FrameStrobe[17]
  PIN FrameStrobe[18]
    DIRECTION INPUT ;
    USE SIGNAL ;
    ANTENNAGATEAREA 0.744000 ;
    PORT
      LAYER met2 ;
        RECT 142.230 0.000 142.510 0.280 ;
    END
  END FrameStrobe[18]
  PIN FrameStrobe[19]
    DIRECTION INPUT ;
    USE SIGNAL ;
    ANTENNAGATEAREA 1.065900 ;
    ANTENNADIFFAREA 0.869400 ;
    PORT
      LAYER met2 ;
        RECT 143.150 0.000 143.430 0.280 ;
    END
  END FrameStrobe[19]
  PIN FrameStrobe[1]
    DIRECTION INPUT ;
    USE SIGNAL ;
    ANTENNAGATEAREA 0.585000 ;
    PORT
      LAYER met2 ;
        RECT 126.590 0.000 126.870 0.280 ;
    END
  END FrameStrobe[1]
  PIN FrameStrobe[2]
    DIRECTION INPUT ;
    USE SIGNAL ;
    ANTENNAGATEAREA 0.647700 ;
    ANTENNADIFFAREA 0.434700 ;
    PORT
      LAYER met2 ;
        RECT 127.510 0.000 127.790 0.280 ;
    END
  END FrameStrobe[2]
  PIN FrameStrobe[3]
    DIRECTION INPUT ;
    USE SIGNAL ;
    ANTENNAGATEAREA 0.647700 ;
    ANTENNADIFFAREA 0.434700 ;
    PORT
      LAYER met2 ;
        RECT 128.430 0.000 128.710 0.280 ;
    END
  END FrameStrobe[3]
  PIN FrameStrobe[4]
    DIRECTION INPUT ;
    USE SIGNAL ;
    ANTENNAGATEAREA 0.213000 ;
    PORT
      LAYER met2 ;
        RECT 129.350 0.000 129.630 0.280 ;
    END
  END FrameStrobe[4]
  PIN FrameStrobe[5]
    DIRECTION INPUT ;
    USE SIGNAL ;
    ANTENNAGATEAREA 0.372000 ;
    PORT
      LAYER met2 ;
        RECT 130.270 0.000 130.550 0.280 ;
    END
  END FrameStrobe[5]
  PIN FrameStrobe[6]
    DIRECTION INPUT ;
    USE SIGNAL ;
    ANTENNAGATEAREA 0.690000 ;
    PORT
      LAYER met2 ;
        RECT 131.190 0.000 131.470 0.280 ;
    END
  END FrameStrobe[6]
  PIN FrameStrobe[7]
    DIRECTION INPUT ;
    USE SIGNAL ;
    ANTENNAGATEAREA 0.986700 ;
    ANTENNADIFFAREA 0.434700 ;
    PORT
      LAYER met2 ;
        RECT 132.110 0.000 132.390 0.280 ;
    END
  END FrameStrobe[7]
  PIN FrameStrobe[8]
    DIRECTION INPUT ;
    USE SIGNAL ;
    ANTENNAGATEAREA 0.673500 ;
    PORT
      LAYER met2 ;
        RECT 133.030 0.000 133.310 0.280 ;
    END
  END FrameStrobe[8]
  PIN FrameStrobe[9]
    DIRECTION INPUT ;
    USE SIGNAL ;
    ANTENNAGATEAREA 0.552000 ;
    PORT
      LAYER met2 ;
        RECT 133.950 0.000 134.230 0.280 ;
    END
  END FrameStrobe[9]
  PIN FrameStrobe_O[0]
    DIRECTION OUTPUT ;
    USE SIGNAL ;
    ANTENNADIFFAREA 0.445500 ;
    PORT
      LAYER met2 ;
        RECT 125.670 259.480 125.950 259.760 ;
    END
  END FrameStrobe_O[0]
  PIN FrameStrobe_O[10]
    DIRECTION OUTPUT ;
    USE SIGNAL ;
    ANTENNADIFFAREA 0.445500 ;
    PORT
      LAYER met2 ;
        RECT 134.870 259.480 135.150 259.760 ;
    END
  END FrameStrobe_O[10]
  PIN FrameStrobe_O[11]
    DIRECTION OUTPUT ;
    USE SIGNAL ;
    ANTENNADIFFAREA 0.445500 ;
    PORT
      LAYER met2 ;
        RECT 135.790 259.480 136.070 259.760 ;
    END
  END FrameStrobe_O[11]
  PIN FrameStrobe_O[12]
    DIRECTION OUTPUT ;
    USE SIGNAL ;
    ANTENNADIFFAREA 0.445500 ;
    PORT
      LAYER met2 ;
        RECT 136.710 259.480 136.990 259.760 ;
    END
  END FrameStrobe_O[12]
  PIN FrameStrobe_O[13]
    DIRECTION OUTPUT ;
    USE SIGNAL ;
    ANTENNADIFFAREA 0.445500 ;
    PORT
      LAYER met2 ;
        RECT 137.630 259.480 137.910 259.760 ;
    END
  END FrameStrobe_O[13]
  PIN FrameStrobe_O[14]
    DIRECTION OUTPUT ;
    USE SIGNAL ;
    ANTENNADIFFAREA 0.445500 ;
    PORT
      LAYER met2 ;
        RECT 138.550 259.480 138.830 259.760 ;
    END
  END FrameStrobe_O[14]
  PIN FrameStrobe_O[15]
    DIRECTION OUTPUT ;
    USE SIGNAL ;
    ANTENNADIFFAREA 0.445500 ;
    PORT
      LAYER met2 ;
        RECT 139.470 259.480 139.750 259.760 ;
    END
  END FrameStrobe_O[15]
  PIN FrameStrobe_O[16]
    DIRECTION OUTPUT ;
    USE SIGNAL ;
    ANTENNADIFFAREA 0.445500 ;
    PORT
      LAYER met2 ;
        RECT 140.390 259.480 140.670 259.760 ;
    END
  END FrameStrobe_O[16]
  PIN FrameStrobe_O[17]
    DIRECTION OUTPUT ;
    USE SIGNAL ;
    ANTENNADIFFAREA 0.445500 ;
    PORT
      LAYER met2 ;
        RECT 141.310 259.480 141.590 259.760 ;
    END
  END FrameStrobe_O[17]
  PIN FrameStrobe_O[18]
    DIRECTION OUTPUT ;
    USE SIGNAL ;
    ANTENNADIFFAREA 0.445500 ;
    PORT
      LAYER met2 ;
        RECT 142.230 259.480 142.510 259.760 ;
    END
  END FrameStrobe_O[18]
  PIN FrameStrobe_O[19]
    DIRECTION OUTPUT ;
    USE SIGNAL ;
    ANTENNADIFFAREA 0.445500 ;
    PORT
      LAYER met2 ;
        RECT 143.150 259.480 143.430 259.760 ;
    END
  END FrameStrobe_O[19]
  PIN FrameStrobe_O[1]
    DIRECTION OUTPUT ;
    USE SIGNAL ;
    ANTENNADIFFAREA 0.445500 ;
    PORT
      LAYER met2 ;
        RECT 126.590 259.480 126.870 259.760 ;
    END
  END FrameStrobe_O[1]
  PIN FrameStrobe_O[2]
    DIRECTION OUTPUT ;
    USE SIGNAL ;
    ANTENNADIFFAREA 0.445500 ;
    PORT
      LAYER met2 ;
        RECT 127.510 259.480 127.790 259.760 ;
    END
  END FrameStrobe_O[2]
  PIN FrameStrobe_O[3]
    DIRECTION OUTPUT ;
    USE SIGNAL ;
    ANTENNADIFFAREA 0.445500 ;
    PORT
      LAYER met2 ;
        RECT 128.430 259.480 128.710 259.760 ;
    END
  END FrameStrobe_O[3]
  PIN FrameStrobe_O[4]
    DIRECTION OUTPUT ;
    USE SIGNAL ;
    ANTENNADIFFAREA 0.445500 ;
    PORT
      LAYER met2 ;
        RECT 129.350 259.480 129.630 259.760 ;
    END
  END FrameStrobe_O[4]
  PIN FrameStrobe_O[5]
    DIRECTION OUTPUT ;
    USE SIGNAL ;
    ANTENNADIFFAREA 0.445500 ;
    PORT
      LAYER met2 ;
        RECT 130.270 259.480 130.550 259.760 ;
    END
  END FrameStrobe_O[5]
  PIN FrameStrobe_O[6]
    DIRECTION OUTPUT ;
    USE SIGNAL ;
    ANTENNADIFFAREA 0.445500 ;
    PORT
      LAYER met2 ;
        RECT 131.190 259.480 131.470 259.760 ;
    END
  END FrameStrobe_O[6]
  PIN FrameStrobe_O[7]
    DIRECTION OUTPUT ;
    USE SIGNAL ;
    ANTENNADIFFAREA 0.445500 ;
    PORT
      LAYER met2 ;
        RECT 132.110 259.480 132.390 259.760 ;
    END
  END FrameStrobe_O[7]
  PIN FrameStrobe_O[8]
    DIRECTION OUTPUT ;
    USE SIGNAL ;
    ANTENNADIFFAREA 0.445500 ;
    PORT
      LAYER met2 ;
        RECT 133.030 259.480 133.310 259.760 ;
    END
  END FrameStrobe_O[8]
  PIN FrameStrobe_O[9]
    DIRECTION OUTPUT ;
    USE SIGNAL ;
    ANTENNADIFFAREA 0.445500 ;
    PORT
      LAYER met2 ;
        RECT 133.950 259.480 134.230 259.760 ;
    END
  END FrameStrobe_O[9]
  PIN N1BEG[0]
    DIRECTION OUTPUT ;
    USE SIGNAL ;
    ANTENNADIFFAREA 0.891000 ;
    PORT
      LAYER met2 ;
        RECT 28.150 259.480 28.430 259.760 ;
    END
  END N1BEG[0]
  PIN N1BEG[1]
    DIRECTION OUTPUT ;
    USE SIGNAL ;
    ANTENNADIFFAREA 0.891000 ;
    PORT
      LAYER met2 ;
        RECT 29.070 259.480 29.350 259.760 ;
    END
  END N1BEG[1]
  PIN N1BEG[2]
    DIRECTION OUTPUT ;
    USE SIGNAL ;
    ANTENNADIFFAREA 1.782000 ;
    PORT
      LAYER met2 ;
        RECT 29.990 259.480 30.270 259.760 ;
    END
  END N1BEG[2]
  PIN N1BEG[3]
    DIRECTION OUTPUT ;
    USE SIGNAL ;
    ANTENNADIFFAREA 0.891000 ;
    PORT
      LAYER met2 ;
        RECT 30.910 259.480 31.190 259.760 ;
    END
  END N1BEG[3]
  PIN N1END[0]
    DIRECTION INPUT ;
    USE SIGNAL ;
    ANTENNAGATEAREA 0.213000 ;
    PORT
      LAYER met2 ;
        RECT 28.150 0.000 28.430 0.280 ;
    END
  END N1END[0]
  PIN N1END[1]
    DIRECTION INPUT ;
    USE SIGNAL ;
    ANTENNAGATEAREA 0.717000 ;
    PORT
      LAYER met2 ;
        RECT 29.070 0.000 29.350 0.280 ;
    END
  END N1END[1]
  PIN N1END[2]
    DIRECTION INPUT ;
    USE SIGNAL ;
    ANTENNAGATEAREA 0.460500 ;
    PORT
      LAYER met2 ;
        RECT 29.990 0.000 30.270 0.280 ;
    END
  END N1END[2]
  PIN N1END[3]
    DIRECTION INPUT ;
    USE SIGNAL ;
    ANTENNAGATEAREA 0.213000 ;
    PORT
      LAYER met2 ;
        RECT 30.910 0.000 31.190 0.280 ;
    END
  END N1END[3]
  PIN N2BEG[0]
    DIRECTION OUTPUT ;
    USE SIGNAL ;
    ANTENNADIFFAREA 0.891000 ;
    PORT
      LAYER met2 ;
        RECT 31.830 259.480 32.110 259.760 ;
    END
  END N2BEG[0]
  PIN N2BEG[1]
    DIRECTION OUTPUT ;
    USE SIGNAL ;
    ANTENNADIFFAREA 0.891000 ;
    PORT
      LAYER met2 ;
        RECT 32.750 259.480 33.030 259.760 ;
    END
  END N2BEG[1]
  PIN N2BEG[2]
    DIRECTION OUTPUT ;
    USE SIGNAL ;
    ANTENNADIFFAREA 1.336500 ;
    PORT
      LAYER met2 ;
        RECT 33.670 259.480 33.950 259.760 ;
    END
  END N2BEG[2]
  PIN N2BEG[3]
    DIRECTION OUTPUT ;
    USE SIGNAL ;
    ANTENNADIFFAREA 0.891000 ;
    PORT
      LAYER met2 ;
        RECT 34.590 259.480 34.870 259.760 ;
    END
  END N2BEG[3]
  PIN N2BEG[4]
    DIRECTION OUTPUT ;
    USE SIGNAL ;
    ANTENNADIFFAREA 0.795200 ;
    PORT
      LAYER met2 ;
        RECT 35.510 259.480 35.790 259.760 ;
    END
  END N2BEG[4]
  PIN N2BEG[5]
    DIRECTION OUTPUT ;
    USE SIGNAL ;
    ANTENNADIFFAREA 1.336500 ;
    PORT
      LAYER met2 ;
        RECT 36.430 259.480 36.710 259.760 ;
    END
  END N2BEG[5]
  PIN N2BEG[6]
    DIRECTION OUTPUT ;
    USE SIGNAL ;
    ANTENNADIFFAREA 1.782000 ;
    PORT
      LAYER met2 ;
        RECT 37.350 259.480 37.630 259.760 ;
    END
  END N2BEG[6]
  PIN N2BEG[7]
    DIRECTION OUTPUT ;
    USE SIGNAL ;
    ANTENNADIFFAREA 0.891000 ;
    PORT
      LAYER met2 ;
        RECT 38.270 259.480 38.550 259.760 ;
    END
  END N2BEG[7]
  PIN N2BEGb[0]
    DIRECTION OUTPUT ;
    USE SIGNAL ;
    ANTENNADIFFAREA 0.445500 ;
    PORT
      LAYER met2 ;
        RECT 39.190 259.480 39.470 259.760 ;
    END
  END N2BEGb[0]
  PIN N2BEGb[1]
    DIRECTION OUTPUT ;
    USE SIGNAL ;
    ANTENNADIFFAREA 0.445500 ;
    PORT
      LAYER met2 ;
        RECT 40.110 259.480 40.390 259.760 ;
    END
  END N2BEGb[1]
  PIN N2BEGb[2]
    DIRECTION OUTPUT ;
    USE SIGNAL ;
    ANTENNADIFFAREA 0.445500 ;
    PORT
      LAYER met2 ;
        RECT 41.030 259.480 41.310 259.760 ;
    END
  END N2BEGb[2]
  PIN N2BEGb[3]
    DIRECTION OUTPUT ;
    USE SIGNAL ;
    ANTENNADIFFAREA 0.445500 ;
    PORT
      LAYER met2 ;
        RECT 41.950 259.480 42.230 259.760 ;
    END
  END N2BEGb[3]
  PIN N2BEGb[4]
    DIRECTION OUTPUT ;
    USE SIGNAL ;
    ANTENNADIFFAREA 0.445500 ;
    PORT
      LAYER met2 ;
        RECT 42.870 259.480 43.150 259.760 ;
    END
  END N2BEGb[4]
  PIN N2BEGb[5]
    DIRECTION OUTPUT ;
    USE SIGNAL ;
    ANTENNADIFFAREA 0.445500 ;
    PORT
      LAYER met2 ;
        RECT 43.790 259.480 44.070 259.760 ;
    END
  END N2BEGb[5]
  PIN N2BEGb[6]
    DIRECTION OUTPUT ;
    USE SIGNAL ;
    ANTENNADIFFAREA 0.445500 ;
    PORT
      LAYER met2 ;
        RECT 44.710 259.480 44.990 259.760 ;
    END
  END N2BEGb[6]
  PIN N2BEGb[7]
    DIRECTION OUTPUT ;
    USE SIGNAL ;
    ANTENNADIFFAREA 0.445500 ;
    PORT
      LAYER met2 ;
        RECT 45.630 259.480 45.910 259.760 ;
    END
  END N2BEGb[7]
  PIN N2END[0]
    DIRECTION INPUT ;
    USE SIGNAL ;
    ANTENNAGATEAREA 1.256700 ;
    ANTENNADIFFAREA 0.434700 ;
    PORT
      LAYER met2 ;
        RECT 39.190 0.000 39.470 0.280 ;
    END
  END N2END[0]
  PIN N2END[1]
    DIRECTION INPUT ;
    USE SIGNAL ;
    ANTENNAGATEAREA 0.696000 ;
    PORT
      LAYER met2 ;
        RECT 40.110 0.000 40.390 0.280 ;
    END
  END N2END[1]
  PIN N2END[2]
    DIRECTION INPUT ;
    USE SIGNAL ;
    ANTENNAGATEAREA 0.663000 ;
    PORT
      LAYER met2 ;
        RECT 41.030 0.000 41.310 0.280 ;
    END
  END N2END[2]
  PIN N2END[3]
    DIRECTION INPUT ;
    USE SIGNAL ;
    ANTENNAGATEAREA 0.822000 ;
    PORT
      LAYER met2 ;
        RECT 41.950 0.000 42.230 0.280 ;
    END
  END N2END[3]
  PIN N2END[4]
    DIRECTION INPUT ;
    USE SIGNAL ;
    ANTENNAGATEAREA 0.822000 ;
    PORT
      LAYER met2 ;
        RECT 42.870 0.000 43.150 0.280 ;
    END
  END N2END[4]
  PIN N2END[5]
    DIRECTION INPUT ;
    USE SIGNAL ;
    ANTENNAGATEAREA 0.663000 ;
    PORT
      LAYER met2 ;
        RECT 43.790 0.000 44.070 0.280 ;
    END
  END N2END[5]
  PIN N2END[6]
    DIRECTION INPUT ;
    USE SIGNAL ;
    ANTENNAGATEAREA 1.532400 ;
    ANTENNADIFFAREA 0.869400 ;
    PORT
      LAYER met2 ;
        RECT 44.710 0.000 44.990 0.280 ;
    END
  END N2END[6]
  PIN N2END[7]
    DIRECTION INPUT ;
    USE SIGNAL ;
    ANTENNAGATEAREA 0.822000 ;
    PORT
      LAYER met2 ;
        RECT 45.630 0.000 45.910 0.280 ;
    END
  END N2END[7]
  PIN N2MID[0]
    DIRECTION INPUT ;
    USE SIGNAL ;
    ANTENNAGATEAREA 0.690000 ;
    PORT
      LAYER met2 ;
        RECT 31.830 0.000 32.110 0.280 ;
    END
  END N2MID[0]
  PIN N2MID[1]
    DIRECTION INPUT ;
    USE SIGNAL ;
    ANTENNAGATEAREA 0.850500 ;
    PORT
      LAYER met2 ;
        RECT 32.750 0.000 33.030 0.280 ;
    END
  END N2MID[1]
  PIN N2MID[2]
    DIRECTION INPUT ;
    USE SIGNAL ;
    ANTENNAGATEAREA 2.379300 ;
    ANTENNADIFFAREA 1.738800 ;
    PORT
      LAYER met2 ;
        RECT 33.670 0.000 33.950 0.280 ;
    END
  END N2MID[2]
  PIN N2MID[3]
    DIRECTION INPUT ;
    USE SIGNAL ;
    ANTENNAGATEAREA 0.832500 ;
    PORT
      LAYER met2 ;
        RECT 34.590 0.000 34.870 0.280 ;
    END
  END N2MID[3]
  PIN N2MID[4]
    DIRECTION INPUT ;
    USE SIGNAL ;
    ANTENNAGATEAREA 1.096500 ;
    PORT
      LAYER met2 ;
        RECT 35.510 0.000 35.790 0.280 ;
    END
  END N2MID[4]
  PIN N2MID[5]
    DIRECTION INPUT ;
    USE SIGNAL ;
    ANTENNAGATEAREA 0.750000 ;
    PORT
      LAYER met2 ;
        RECT 36.430 0.000 36.710 0.280 ;
    END
  END N2MID[5]
  PIN N2MID[6]
    DIRECTION INPUT ;
    USE SIGNAL ;
    ANTENNAGATEAREA 0.624000 ;
    PORT
      LAYER met2 ;
        RECT 37.350 0.000 37.630 0.280 ;
    END
  END N2MID[6]
  PIN N2MID[7]
    DIRECTION INPUT ;
    USE SIGNAL ;
    ANTENNAGATEAREA 0.783000 ;
    PORT
      LAYER met2 ;
        RECT 38.270 0.000 38.550 0.280 ;
    END
  END N2MID[7]
  PIN N4BEG[0]
    DIRECTION OUTPUT ;
    USE SIGNAL ;
    ANTENNADIFFAREA 0.445500 ;
    PORT
      LAYER met2 ;
        RECT 46.550 259.480 46.830 259.760 ;
    END
  END N4BEG[0]
  PIN N4BEG[10]
    DIRECTION OUTPUT ;
    USE SIGNAL ;
    ANTENNADIFFAREA 0.445500 ;
    PORT
      LAYER met2 ;
        RECT 55.750 259.480 56.030 259.760 ;
    END
  END N4BEG[10]
  PIN N4BEG[11]
    DIRECTION OUTPUT ;
    USE SIGNAL ;
    ANTENNADIFFAREA 0.445500 ;
    PORT
      LAYER met2 ;
        RECT 56.670 259.480 56.950 259.760 ;
    END
  END N4BEG[11]
  PIN N4BEG[12]
    DIRECTION OUTPUT ;
    USE SIGNAL ;
    ANTENNADIFFAREA 0.891000 ;
    PORT
      LAYER met2 ;
        RECT 57.590 259.480 57.870 259.760 ;
    END
  END N4BEG[12]
  PIN N4BEG[13]
    DIRECTION OUTPUT ;
    USE SIGNAL ;
    ANTENNADIFFAREA 0.891000 ;
    PORT
      LAYER met2 ;
        RECT 58.510 259.480 58.790 259.760 ;
    END
  END N4BEG[13]
  PIN N4BEG[14]
    DIRECTION OUTPUT ;
    USE SIGNAL ;
    ANTENNADIFFAREA 0.795200 ;
    PORT
      LAYER met2 ;
        RECT 59.430 259.480 59.710 259.760 ;
    END
  END N4BEG[14]
  PIN N4BEG[15]
    DIRECTION OUTPUT ;
    USE SIGNAL ;
    ANTENNADIFFAREA 1.782000 ;
    PORT
      LAYER met2 ;
        RECT 60.350 259.480 60.630 259.760 ;
    END
  END N4BEG[15]
  PIN N4BEG[1]
    DIRECTION OUTPUT ;
    USE SIGNAL ;
    ANTENNADIFFAREA 0.445500 ;
    PORT
      LAYER met2 ;
        RECT 47.470 259.480 47.750 259.760 ;
    END
  END N4BEG[1]
  PIN N4BEG[2]
    DIRECTION OUTPUT ;
    USE SIGNAL ;
    ANTENNADIFFAREA 0.445500 ;
    PORT
      LAYER met2 ;
        RECT 48.390 259.480 48.670 259.760 ;
    END
  END N4BEG[2]
  PIN N4BEG[3]
    DIRECTION OUTPUT ;
    USE SIGNAL ;
    ANTENNADIFFAREA 0.445500 ;
    PORT
      LAYER met2 ;
        RECT 49.310 259.480 49.590 259.760 ;
    END
  END N4BEG[3]
  PIN N4BEG[4]
    DIRECTION OUTPUT ;
    USE SIGNAL ;
    ANTENNADIFFAREA 0.445500 ;
    PORT
      LAYER met2 ;
        RECT 50.230 259.480 50.510 259.760 ;
    END
  END N4BEG[4]
  PIN N4BEG[5]
    DIRECTION OUTPUT ;
    USE SIGNAL ;
    ANTENNADIFFAREA 0.445500 ;
    PORT
      LAYER met2 ;
        RECT 51.150 259.480 51.430 259.760 ;
    END
  END N4BEG[5]
  PIN N4BEG[6]
    DIRECTION OUTPUT ;
    USE SIGNAL ;
    ANTENNADIFFAREA 0.445500 ;
    PORT
      LAYER met2 ;
        RECT 52.070 259.480 52.350 259.760 ;
    END
  END N4BEG[6]
  PIN N4BEG[7]
    DIRECTION OUTPUT ;
    USE SIGNAL ;
    ANTENNADIFFAREA 0.445500 ;
    PORT
      LAYER met2 ;
        RECT 52.990 259.480 53.270 259.760 ;
    END
  END N4BEG[7]
  PIN N4BEG[8]
    DIRECTION OUTPUT ;
    USE SIGNAL ;
    ANTENNADIFFAREA 0.445500 ;
    PORT
      LAYER met2 ;
        RECT 53.910 259.480 54.190 259.760 ;
    END
  END N4BEG[8]
  PIN N4BEG[9]
    DIRECTION OUTPUT ;
    USE SIGNAL ;
    ANTENNADIFFAREA 0.445500 ;
    PORT
      LAYER met2 ;
        RECT 54.830 259.480 55.110 259.760 ;
    END
  END N4BEG[9]
  PIN N4END[0]
    DIRECTION INPUT ;
    USE SIGNAL ;
    ANTENNAGATEAREA 0.663000 ;
    PORT
      LAYER met2 ;
        RECT 46.550 0.000 46.830 0.280 ;
    END
  END N4END[0]
  PIN N4END[10]
    DIRECTION INPUT ;
    USE SIGNAL ;
    ANTENNAGATEAREA 0.631200 ;
    ANTENNADIFFAREA 0.434700 ;
    PORT
      LAYER met2 ;
        RECT 55.750 0.000 56.030 0.280 ;
    END
  END N4END[10]
  PIN N4END[11]
    DIRECTION INPUT ;
    USE SIGNAL ;
    ANTENNAGATEAREA 0.631200 ;
    ANTENNADIFFAREA 0.434700 ;
    PORT
      LAYER met2 ;
        RECT 56.670 0.000 56.950 0.280 ;
    END
  END N4END[11]
  PIN N4END[12]
    DIRECTION INPUT ;
    USE SIGNAL ;
    ANTENNAGATEAREA 0.631200 ;
    ANTENNADIFFAREA 0.434700 ;
    PORT
      LAYER met2 ;
        RECT 57.590 0.000 57.870 0.280 ;
    END
  END N4END[12]
  PIN N4END[13]
    DIRECTION INPUT ;
    USE SIGNAL ;
    ANTENNAGATEAREA 0.631200 ;
    ANTENNADIFFAREA 0.434700 ;
    PORT
      LAYER met2 ;
        RECT 58.510 0.000 58.790 0.280 ;
    END
  END N4END[13]
  PIN N4END[14]
    DIRECTION INPUT ;
    USE SIGNAL ;
    ANTENNAGATEAREA 0.631200 ;
    ANTENNADIFFAREA 0.434700 ;
    PORT
      LAYER met2 ;
        RECT 59.430 0.000 59.710 0.280 ;
    END
  END N4END[14]
  PIN N4END[15]
    DIRECTION INPUT ;
    USE SIGNAL ;
    ANTENNAGATEAREA 0.631200 ;
    ANTENNADIFFAREA 0.434700 ;
    PORT
      LAYER met2 ;
        RECT 60.350 0.000 60.630 0.280 ;
    END
  END N4END[15]
  PIN N4END[1]
    DIRECTION INPUT ;
    USE SIGNAL ;
    ANTENNAGATEAREA 0.696000 ;
    PORT
      LAYER met2 ;
        RECT 47.470 0.000 47.750 0.280 ;
    END
  END N4END[1]
  PIN N4END[2]
    DIRECTION INPUT ;
    USE SIGNAL ;
    ANTENNAGATEAREA 0.696000 ;
    PORT
      LAYER met2 ;
        RECT 48.390 0.000 48.670 0.280 ;
    END
  END N4END[2]
  PIN N4END[3]
    DIRECTION INPUT ;
    USE SIGNAL ;
    ANTENNAGATEAREA 1.064700 ;
    ANTENNADIFFAREA 0.434700 ;
    PORT
      LAYER met2 ;
        RECT 49.310 0.000 49.590 0.280 ;
    END
  END N4END[3]
  PIN N4END[4]
    DIRECTION INPUT ;
    USE SIGNAL ;
    ANTENNAGATEAREA 0.631200 ;
    ANTENNADIFFAREA 0.434700 ;
    PORT
      LAYER met2 ;
        RECT 50.230 0.000 50.510 0.280 ;
    END
  END N4END[4]
  PIN N4END[5]
    DIRECTION INPUT ;
    USE SIGNAL ;
    ANTENNAGATEAREA 0.631200 ;
    ANTENNADIFFAREA 0.434700 ;
    PORT
      LAYER met2 ;
        RECT 51.150 0.000 51.430 0.280 ;
    END
  END N4END[5]
  PIN N4END[6]
    DIRECTION INPUT ;
    USE SIGNAL ;
    ANTENNAGATEAREA 0.631200 ;
    ANTENNADIFFAREA 0.434700 ;
    PORT
      LAYER met2 ;
        RECT 52.070 0.000 52.350 0.280 ;
    END
  END N4END[6]
  PIN N4END[7]
    DIRECTION INPUT ;
    USE SIGNAL ;
    ANTENNAGATEAREA 0.631200 ;
    ANTENNADIFFAREA 0.434700 ;
    PORT
      LAYER met2 ;
        RECT 52.990 0.000 53.270 0.280 ;
    END
  END N4END[7]
  PIN N4END[8]
    DIRECTION INPUT ;
    USE SIGNAL ;
    ANTENNAGATEAREA 0.631200 ;
    ANTENNADIFFAREA 0.434700 ;
    PORT
      LAYER met2 ;
        RECT 53.910 0.000 54.190 0.280 ;
    END
  END N4END[8]
  PIN N4END[9]
    DIRECTION INPUT ;
    USE SIGNAL ;
    ANTENNAGATEAREA 0.631200 ;
    ANTENNADIFFAREA 0.434700 ;
    PORT
      LAYER met2 ;
        RECT 54.830 0.000 55.110 0.280 ;
    END
  END N4END[9]
  PIN NN4BEG[0]
    DIRECTION OUTPUT ;
    USE SIGNAL ;
    ANTENNADIFFAREA 0.445500 ;
    PORT
      LAYER met2 ;
        RECT 61.270 259.480 61.550 259.760 ;
    END
  END NN4BEG[0]
  PIN NN4BEG[10]
    DIRECTION OUTPUT ;
    USE SIGNAL ;
    ANTENNADIFFAREA 0.445500 ;
    PORT
      LAYER met2 ;
        RECT 70.470 259.480 70.750 259.760 ;
    END
  END NN4BEG[10]
  PIN NN4BEG[11]
    DIRECTION OUTPUT ;
    USE SIGNAL ;
    ANTENNADIFFAREA 0.445500 ;
    PORT
      LAYER met2 ;
        RECT 71.390 259.480 71.670 259.760 ;
    END
  END NN4BEG[11]
  PIN NN4BEG[12]
    DIRECTION OUTPUT ;
    USE SIGNAL ;
    ANTENNADIFFAREA 1.336500 ;
    PORT
      LAYER met2 ;
        RECT 72.310 259.480 72.590 259.760 ;
    END
  END NN4BEG[12]
  PIN NN4BEG[13]
    DIRECTION OUTPUT ;
    USE SIGNAL ;
    ANTENNADIFFAREA 1.336500 ;
    PORT
      LAYER met2 ;
        RECT 73.230 259.480 73.510 259.760 ;
    END
  END NN4BEG[13]
  PIN NN4BEG[14]
    DIRECTION OUTPUT ;
    USE SIGNAL ;
    ANTENNADIFFAREA 1.336500 ;
    PORT
      LAYER met2 ;
        RECT 74.150 259.480 74.430 259.760 ;
    END
  END NN4BEG[14]
  PIN NN4BEG[15]
    DIRECTION OUTPUT ;
    USE SIGNAL ;
    ANTENNADIFFAREA 1.782000 ;
    PORT
      LAYER met2 ;
        RECT 75.070 259.480 75.350 259.760 ;
    END
  END NN4BEG[15]
  PIN NN4BEG[1]
    DIRECTION OUTPUT ;
    USE SIGNAL ;
    ANTENNADIFFAREA 0.445500 ;
    PORT
      LAYER met2 ;
        RECT 62.190 259.480 62.470 259.760 ;
    END
  END NN4BEG[1]
  PIN NN4BEG[2]
    DIRECTION OUTPUT ;
    USE SIGNAL ;
    ANTENNADIFFAREA 0.445500 ;
    PORT
      LAYER met2 ;
        RECT 63.110 259.480 63.390 259.760 ;
    END
  END NN4BEG[2]
  PIN NN4BEG[3]
    DIRECTION OUTPUT ;
    USE SIGNAL ;
    ANTENNADIFFAREA 0.445500 ;
    PORT
      LAYER met2 ;
        RECT 64.030 259.480 64.310 259.760 ;
    END
  END NN4BEG[3]
  PIN NN4BEG[4]
    DIRECTION OUTPUT ;
    USE SIGNAL ;
    ANTENNADIFFAREA 0.445500 ;
    PORT
      LAYER met2 ;
        RECT 64.950 259.480 65.230 259.760 ;
    END
  END NN4BEG[4]
  PIN NN4BEG[5]
    DIRECTION OUTPUT ;
    USE SIGNAL ;
    ANTENNADIFFAREA 0.445500 ;
    PORT
      LAYER met2 ;
        RECT 65.870 259.480 66.150 259.760 ;
    END
  END NN4BEG[5]
  PIN NN4BEG[6]
    DIRECTION OUTPUT ;
    USE SIGNAL ;
    ANTENNADIFFAREA 0.445500 ;
    PORT
      LAYER met2 ;
        RECT 66.790 259.480 67.070 259.760 ;
    END
  END NN4BEG[6]
  PIN NN4BEG[7]
    DIRECTION OUTPUT ;
    USE SIGNAL ;
    ANTENNADIFFAREA 0.445500 ;
    PORT
      LAYER met2 ;
        RECT 67.710 259.480 67.990 259.760 ;
    END
  END NN4BEG[7]
  PIN NN4BEG[8]
    DIRECTION OUTPUT ;
    USE SIGNAL ;
    ANTENNADIFFAREA 0.445500 ;
    PORT
      LAYER met2 ;
        RECT 68.630 259.480 68.910 259.760 ;
    END
  END NN4BEG[8]
  PIN NN4BEG[9]
    DIRECTION OUTPUT ;
    USE SIGNAL ;
    ANTENNADIFFAREA 0.445500 ;
    PORT
      LAYER met2 ;
        RECT 69.550 259.480 69.830 259.760 ;
    END
  END NN4BEG[9]
  PIN NN4END[0]
    DIRECTION INPUT ;
    USE SIGNAL ;
    ANTENNAGATEAREA 0.444000 ;
    PORT
      LAYER met2 ;
        RECT 61.270 0.000 61.550 0.280 ;
    END
  END NN4END[0]
  PIN NN4END[10]
    DIRECTION INPUT ;
    USE SIGNAL ;
    ANTENNAGATEAREA 0.631200 ;
    ANTENNADIFFAREA 0.434700 ;
    PORT
      LAYER met2 ;
        RECT 70.470 0.000 70.750 0.280 ;
    END
  END NN4END[10]
  PIN NN4END[11]
    DIRECTION INPUT ;
    USE SIGNAL ;
    ANTENNAGATEAREA 0.631200 ;
    ANTENNADIFFAREA 0.434700 ;
    PORT
      LAYER met2 ;
        RECT 71.390 0.000 71.670 0.280 ;
    END
  END NN4END[11]
  PIN NN4END[12]
    DIRECTION INPUT ;
    USE SIGNAL ;
    ANTENNAGATEAREA 0.631200 ;
    ANTENNADIFFAREA 0.434700 ;
    PORT
      LAYER met2 ;
        RECT 72.310 0.000 72.590 0.280 ;
    END
  END NN4END[12]
  PIN NN4END[13]
    DIRECTION INPUT ;
    USE SIGNAL ;
    ANTENNAGATEAREA 0.631200 ;
    ANTENNADIFFAREA 0.434700 ;
    PORT
      LAYER met2 ;
        RECT 73.230 0.000 73.510 0.280 ;
    END
  END NN4END[13]
  PIN NN4END[14]
    DIRECTION INPUT ;
    USE SIGNAL ;
    ANTENNAGATEAREA 0.631200 ;
    ANTENNADIFFAREA 0.434700 ;
    PORT
      LAYER met2 ;
        RECT 74.150 0.000 74.430 0.280 ;
    END
  END NN4END[14]
  PIN NN4END[15]
    DIRECTION INPUT ;
    USE SIGNAL ;
    ANTENNAGATEAREA 0.631200 ;
    ANTENNADIFFAREA 0.434700 ;
    PORT
      LAYER met2 ;
        RECT 75.070 0.000 75.350 0.280 ;
    END
  END NN4END[15]
  PIN NN4END[1]
    DIRECTION INPUT ;
    USE SIGNAL ;
    ANTENNAGATEAREA 1.748100 ;
    ANTENNADIFFAREA 1.304100 ;
    PORT
      LAYER met2 ;
        RECT 62.190 0.000 62.470 0.280 ;
    END
  END NN4END[1]
  PIN NN4END[2]
    DIRECTION INPUT ;
    USE SIGNAL ;
    ANTENNAGATEAREA 0.444000 ;
    PORT
      LAYER met2 ;
        RECT 63.110 0.000 63.390 0.280 ;
    END
  END NN4END[2]
  PIN NN4END[3]
    DIRECTION INPUT ;
    USE SIGNAL ;
    ANTENNAGATEAREA 0.444000 ;
    PORT
      LAYER met2 ;
        RECT 64.030 0.000 64.310 0.280 ;
    END
  END NN4END[3]
  PIN NN4END[4]
    DIRECTION INPUT ;
    USE SIGNAL ;
    ANTENNAGATEAREA 0.631200 ;
    ANTENNADIFFAREA 0.434700 ;
    PORT
      LAYER met2 ;
        RECT 64.950 0.000 65.230 0.280 ;
    END
  END NN4END[4]
  PIN NN4END[5]
    DIRECTION INPUT ;
    USE SIGNAL ;
    ANTENNAGATEAREA 0.631200 ;
    ANTENNADIFFAREA 0.434700 ;
    PORT
      LAYER met2 ;
        RECT 65.870 0.000 66.150 0.280 ;
    END
  END NN4END[5]
  PIN NN4END[6]
    DIRECTION INPUT ;
    USE SIGNAL ;
    ANTENNAGATEAREA 0.631200 ;
    ANTENNADIFFAREA 0.434700 ;
    PORT
      LAYER met2 ;
        RECT 66.790 0.000 67.070 0.280 ;
    END
  END NN4END[6]
  PIN NN4END[7]
    DIRECTION INPUT ;
    USE SIGNAL ;
    ANTENNAGATEAREA 0.631200 ;
    ANTENNADIFFAREA 0.434700 ;
    PORT
      LAYER met2 ;
        RECT 67.710 0.000 67.990 0.280 ;
    END
  END NN4END[7]
  PIN NN4END[8]
    DIRECTION INPUT ;
    USE SIGNAL ;
    ANTENNAGATEAREA 0.631200 ;
    ANTENNADIFFAREA 0.434700 ;
    PORT
      LAYER met2 ;
        RECT 68.630 0.000 68.910 0.280 ;
    END
  END NN4END[8]
  PIN NN4END[9]
    DIRECTION INPUT ;
    USE SIGNAL ;
    ANTENNAGATEAREA 0.631200 ;
    ANTENNADIFFAREA 0.434700 ;
    PORT
      LAYER met2 ;
        RECT 69.550 0.000 69.830 0.280 ;
    END
  END NN4END[9]
  PIN S1BEG[0]
    DIRECTION OUTPUT ;
    USE SIGNAL ;
    ANTENNADIFFAREA 0.795200 ;
    PORT
      LAYER met2 ;
        RECT 76.910 0.000 77.190 0.280 ;
    END
  END S1BEG[0]
  PIN S1BEG[1]
    DIRECTION OUTPUT ;
    USE SIGNAL ;
    ANTENNADIFFAREA 0.891000 ;
    PORT
      LAYER met2 ;
        RECT 77.830 0.000 78.110 0.280 ;
    END
  END S1BEG[1]
  PIN S1BEG[2]
    DIRECTION OUTPUT ;
    USE SIGNAL ;
    ANTENNADIFFAREA 1.336500 ;
    PORT
      LAYER met2 ;
        RECT 78.750 0.000 79.030 0.280 ;
    END
  END S1BEG[2]
  PIN S1BEG[3]
    DIRECTION OUTPUT ;
    USE SIGNAL ;
    ANTENNADIFFAREA 0.795200 ;
    PORT
      LAYER met2 ;
        RECT 79.670 0.000 79.950 0.280 ;
    END
  END S1BEG[3]
  PIN S1END[0]
    DIRECTION INPUT ;
    USE SIGNAL ;
    ANTENNAGATEAREA 3.181500 ;
    ANTENNADIFFAREA 2.173500 ;
    PORT
      LAYER met2 ;
        RECT 76.910 259.480 77.190 259.760 ;
    END
  END S1END[0]
  PIN S1END[1]
    DIRECTION INPUT ;
    USE SIGNAL ;
    ANTENNAGATEAREA 1.008000 ;
    PORT
      LAYER met2 ;
        RECT 77.830 259.480 78.110 259.760 ;
    END
  END S1END[1]
  PIN S1END[2]
    DIRECTION INPUT ;
    USE SIGNAL ;
    ANTENNAGATEAREA 2.129400 ;
    ANTENNADIFFAREA 0.869400 ;
    PORT
      LAYER met2 ;
        RECT 78.750 259.480 79.030 259.760 ;
    END
  END S1END[2]
  PIN S1END[3]
    DIRECTION INPUT ;
    USE SIGNAL ;
    ANTENNAGATEAREA 1.260000 ;
    PORT
      LAYER met2 ;
        RECT 79.670 259.480 79.950 259.760 ;
    END
  END S1END[3]
  PIN S2BEG[0]
    DIRECTION OUTPUT ;
    USE SIGNAL ;
    ANTENNADIFFAREA 0.891000 ;
    PORT
      LAYER met2 ;
        RECT 80.590 0.000 80.870 0.280 ;
    END
  END S2BEG[0]
  PIN S2BEG[1]
    DIRECTION OUTPUT ;
    USE SIGNAL ;
    ANTENNADIFFAREA 0.891000 ;
    PORT
      LAYER met2 ;
        RECT 81.510 0.000 81.790 0.280 ;
    END
  END S2BEG[1]
  PIN S2BEG[2]
    DIRECTION OUTPUT ;
    USE SIGNAL ;
    ANTENNADIFFAREA 0.891000 ;
    PORT
      LAYER met2 ;
        RECT 82.430 0.000 82.710 0.280 ;
    END
  END S2BEG[2]
  PIN S2BEG[3]
    DIRECTION OUTPUT ;
    USE SIGNAL ;
    ANTENNADIFFAREA 0.445500 ;
    PORT
      LAYER met2 ;
        RECT 83.350 0.000 83.630 0.280 ;
    END
  END S2BEG[3]
  PIN S2BEG[4]
    DIRECTION OUTPUT ;
    USE SIGNAL ;
    ANTENNADIFFAREA 0.891000 ;
    PORT
      LAYER met2 ;
        RECT 84.270 0.000 84.550 0.280 ;
    END
  END S2BEG[4]
  PIN S2BEG[5]
    DIRECTION OUTPUT ;
    USE SIGNAL ;
    ANTENNADIFFAREA 1.782000 ;
    PORT
      LAYER met2 ;
        RECT 85.190 0.000 85.470 0.280 ;
    END
  END S2BEG[5]
  PIN S2BEG[6]
    DIRECTION OUTPUT ;
    USE SIGNAL ;
    ANTENNADIFFAREA 1.782000 ;
    PORT
      LAYER met2 ;
        RECT 86.110 0.000 86.390 0.280 ;
    END
  END S2BEG[6]
  PIN S2BEG[7]
    DIRECTION OUTPUT ;
    USE SIGNAL ;
    ANTENNADIFFAREA 0.891000 ;
    PORT
      LAYER met2 ;
        RECT 87.030 0.000 87.310 0.280 ;
    END
  END S2BEG[7]
  PIN S2BEGb[0]
    DIRECTION OUTPUT ;
    USE SIGNAL ;
    ANTENNADIFFAREA 0.445500 ;
    PORT
      LAYER met2 ;
        RECT 87.950 0.000 88.230 0.280 ;
    END
  END S2BEGb[0]
  PIN S2BEGb[1]
    DIRECTION OUTPUT ;
    USE SIGNAL ;
    ANTENNADIFFAREA 0.445500 ;
    PORT
      LAYER met2 ;
        RECT 88.870 0.000 89.150 0.280 ;
    END
  END S2BEGb[1]
  PIN S2BEGb[2]
    DIRECTION OUTPUT ;
    USE SIGNAL ;
    ANTENNADIFFAREA 0.445500 ;
    PORT
      LAYER met2 ;
        RECT 89.790 0.000 90.070 0.280 ;
    END
  END S2BEGb[2]
  PIN S2BEGb[3]
    DIRECTION OUTPUT ;
    USE SIGNAL ;
    ANTENNADIFFAREA 0.445500 ;
    PORT
      LAYER met2 ;
        RECT 90.710 0.000 90.990 0.280 ;
    END
  END S2BEGb[3]
  PIN S2BEGb[4]
    DIRECTION OUTPUT ;
    USE SIGNAL ;
    ANTENNADIFFAREA 0.445500 ;
    PORT
      LAYER met2 ;
        RECT 91.630 0.000 91.910 0.280 ;
    END
  END S2BEGb[4]
  PIN S2BEGb[5]
    DIRECTION OUTPUT ;
    USE SIGNAL ;
    ANTENNADIFFAREA 0.445500 ;
    PORT
      LAYER met2 ;
        RECT 92.550 0.000 92.830 0.280 ;
    END
  END S2BEGb[5]
  PIN S2BEGb[6]
    DIRECTION OUTPUT ;
    USE SIGNAL ;
    ANTENNADIFFAREA 0.445500 ;
    PORT
      LAYER met2 ;
        RECT 93.470 0.000 93.750 0.280 ;
    END
  END S2BEGb[6]
  PIN S2BEGb[7]
    DIRECTION OUTPUT ;
    USE SIGNAL ;
    ANTENNADIFFAREA 0.445500 ;
    PORT
      LAYER met2 ;
        RECT 94.390 0.000 94.670 0.280 ;
    END
  END S2BEGb[7]
  PIN S2END[0]
    DIRECTION INPUT ;
    USE SIGNAL ;
    ANTENNAGATEAREA 0.822000 ;
    PORT
      LAYER met2 ;
        RECT 87.950 259.480 88.230 259.760 ;
    END
  END S2END[0]
  PIN S2END[1]
    DIRECTION INPUT ;
    USE SIGNAL ;
    ANTENNAGATEAREA 0.822000 ;
    PORT
      LAYER met2 ;
        RECT 88.870 259.480 89.150 259.760 ;
    END
  END S2END[1]
  PIN S2END[2]
    DIRECTION INPUT ;
    USE SIGNAL ;
    ANTENNAGATEAREA 0.822000 ;
    PORT
      LAYER met2 ;
        RECT 89.790 259.480 90.070 259.760 ;
    END
  END S2END[2]
  PIN S2END[3]
    DIRECTION INPUT ;
    USE SIGNAL ;
    ANTENNAGATEAREA 0.663000 ;
    PORT
      LAYER met2 ;
        RECT 90.710 259.480 90.990 259.760 ;
    END
  END S2END[3]
  PIN S2END[4]
    DIRECTION INPUT ;
    USE SIGNAL ;
    ANTENNAGATEAREA 0.663000 ;
    PORT
      LAYER met2 ;
        RECT 91.630 259.480 91.910 259.760 ;
    END
  END S2END[4]
  PIN S2END[5]
    DIRECTION INPUT ;
    USE SIGNAL ;
    ANTENNAGATEAREA 0.663000 ;
    PORT
      LAYER met2 ;
        RECT 92.550 259.480 92.830 259.760 ;
    END
  END S2END[5]
  PIN S2END[6]
    DIRECTION INPUT ;
    USE SIGNAL ;
    ANTENNAGATEAREA 1.532400 ;
    ANTENNADIFFAREA 0.869400 ;
    PORT
      LAYER met2 ;
        RECT 93.470 259.480 93.750 259.760 ;
    END
  END S2END[6]
  PIN S2END[7]
    DIRECTION INPUT ;
    USE SIGNAL ;
    ANTENNAGATEAREA 0.822000 ;
    PORT
      LAYER met2 ;
        RECT 94.390 259.480 94.670 259.760 ;
    END
  END S2END[7]
  PIN S2MID[0]
    DIRECTION INPUT ;
    USE SIGNAL ;
    ANTENNAGATEAREA 0.673500 ;
    PORT
      LAYER met2 ;
        RECT 80.590 259.480 80.870 259.760 ;
    END
  END S2MID[0]
  PIN S2MID[1]
    DIRECTION INPUT ;
    USE SIGNAL ;
    ANTENNAGATEAREA 0.799500 ;
    PORT
      LAYER met2 ;
        RECT 81.510 259.480 81.790 259.760 ;
    END
  END S2MID[1]
  PIN S2MID[2]
    DIRECTION INPUT ;
    USE SIGNAL ;
    ANTENNAGATEAREA 0.673500 ;
    PORT
      LAYER met2 ;
        RECT 82.430 259.480 82.710 259.760 ;
    END
  END S2MID[2]
  PIN S2MID[3]
    DIRECTION INPUT ;
    USE SIGNAL ;
    ANTENNAGATEAREA 0.849000 ;
    PORT
      LAYER met2 ;
        RECT 83.350 259.480 83.630 259.760 ;
    END
  END S2MID[3]
  PIN S2MID[4]
    DIRECTION INPUT ;
    USE SIGNAL ;
    ANTENNAGATEAREA 0.849000 ;
    PORT
      LAYER met2 ;
        RECT 84.270 259.480 84.550 259.760 ;
    END
  END S2MID[4]
  PIN S2MID[5]
    DIRECTION INPUT ;
    USE SIGNAL ;
    ANTENNAGATEAREA 0.750000 ;
    PORT
      LAYER met2 ;
        RECT 85.190 259.480 85.470 259.760 ;
    END
  END S2MID[5]
  PIN S2MID[6]
    DIRECTION INPUT ;
    USE SIGNAL ;
    ANTENNAGATEAREA 1.091700 ;
    ANTENNADIFFAREA 0.434700 ;
    PORT
      LAYER met2 ;
        RECT 86.110 259.480 86.390 259.760 ;
    END
  END S2MID[6]
  PIN S2MID[7]
    DIRECTION INPUT ;
    USE SIGNAL ;
    ANTENNAGATEAREA 0.783000 ;
    PORT
      LAYER met2 ;
        RECT 87.030 259.480 87.310 259.760 ;
    END
  END S2MID[7]
  PIN S4BEG[0]
    DIRECTION OUTPUT ;
    USE SIGNAL ;
    ANTENNADIFFAREA 0.445500 ;
    PORT
      LAYER met2 ;
        RECT 95.310 0.000 95.590 0.280 ;
    END
  END S4BEG[0]
  PIN S4BEG[10]
    DIRECTION OUTPUT ;
    USE SIGNAL ;
    ANTENNADIFFAREA 0.445500 ;
    PORT
      LAYER met2 ;
        RECT 104.510 0.000 104.790 0.280 ;
    END
  END S4BEG[10]
  PIN S4BEG[11]
    DIRECTION OUTPUT ;
    USE SIGNAL ;
    ANTENNADIFFAREA 0.445500 ;
    PORT
      LAYER met2 ;
        RECT 105.430 0.000 105.710 0.280 ;
    END
  END S4BEG[11]
  PIN S4BEG[12]
    DIRECTION OUTPUT ;
    USE SIGNAL ;
    ANTENNADIFFAREA 0.445500 ;
    PORT
      LAYER met2 ;
        RECT 106.350 0.000 106.630 0.280 ;
    END
  END S4BEG[12]
  PIN S4BEG[13]
    DIRECTION OUTPUT ;
    USE SIGNAL ;
    ANTENNADIFFAREA 0.445500 ;
    PORT
      LAYER met2 ;
        RECT 107.270 0.000 107.550 0.280 ;
    END
  END S4BEG[13]
  PIN S4BEG[14]
    DIRECTION OUTPUT ;
    USE SIGNAL ;
    ANTENNADIFFAREA 0.891000 ;
    PORT
      LAYER met2 ;
        RECT 108.190 0.000 108.470 0.280 ;
    END
  END S4BEG[14]
  PIN S4BEG[15]
    DIRECTION OUTPUT ;
    USE SIGNAL ;
    ANTENNADIFFAREA 0.891000 ;
    PORT
      LAYER met2 ;
        RECT 109.110 0.000 109.390 0.280 ;
    END
  END S4BEG[15]
  PIN S4BEG[1]
    DIRECTION OUTPUT ;
    USE SIGNAL ;
    ANTENNADIFFAREA 0.445500 ;
    PORT
      LAYER met2 ;
        RECT 96.230 0.000 96.510 0.280 ;
    END
  END S4BEG[1]
  PIN S4BEG[2]
    DIRECTION OUTPUT ;
    USE SIGNAL ;
    ANTENNADIFFAREA 0.445500 ;
    PORT
      LAYER met2 ;
        RECT 97.150 0.000 97.430 0.280 ;
    END
  END S4BEG[2]
  PIN S4BEG[3]
    DIRECTION OUTPUT ;
    USE SIGNAL ;
    ANTENNADIFFAREA 0.445500 ;
    PORT
      LAYER met2 ;
        RECT 98.070 0.000 98.350 0.280 ;
    END
  END S4BEG[3]
  PIN S4BEG[4]
    DIRECTION OUTPUT ;
    USE SIGNAL ;
    ANTENNADIFFAREA 0.445500 ;
    PORT
      LAYER met2 ;
        RECT 98.990 0.000 99.270 0.280 ;
    END
  END S4BEG[4]
  PIN S4BEG[5]
    DIRECTION OUTPUT ;
    USE SIGNAL ;
    ANTENNADIFFAREA 0.445500 ;
    PORT
      LAYER met2 ;
        RECT 99.910 0.000 100.190 0.280 ;
    END
  END S4BEG[5]
  PIN S4BEG[6]
    DIRECTION OUTPUT ;
    USE SIGNAL ;
    ANTENNADIFFAREA 0.445500 ;
    PORT
      LAYER met2 ;
        RECT 100.830 0.000 101.110 0.280 ;
    END
  END S4BEG[6]
  PIN S4BEG[7]
    DIRECTION OUTPUT ;
    USE SIGNAL ;
    ANTENNADIFFAREA 0.445500 ;
    PORT
      LAYER met2 ;
        RECT 101.750 0.000 102.030 0.280 ;
    END
  END S4BEG[7]
  PIN S4BEG[8]
    DIRECTION OUTPUT ;
    USE SIGNAL ;
    ANTENNADIFFAREA 0.445500 ;
    PORT
      LAYER met2 ;
        RECT 102.670 0.000 102.950 0.280 ;
    END
  END S4BEG[8]
  PIN S4BEG[9]
    DIRECTION OUTPUT ;
    USE SIGNAL ;
    ANTENNADIFFAREA 0.445500 ;
    PORT
      LAYER met2 ;
        RECT 103.590 0.000 103.870 0.280 ;
    END
  END S4BEG[9]
  PIN S4END[0]
    DIRECTION INPUT ;
    USE SIGNAL ;
    ANTENNAGATEAREA 2.836500 ;
    ANTENNADIFFAREA 2.173500 ;
    PORT
      LAYER met2 ;
        RECT 95.310 259.480 95.590 259.760 ;
    END
  END S4END[0]
  PIN S4END[10]
    DIRECTION INPUT ;
    USE SIGNAL ;
    ANTENNAGATEAREA 0.213000 ;
    PORT
      LAYER met2 ;
        RECT 104.510 259.480 104.790 259.760 ;
    END
  END S4END[10]
  PIN S4END[11]
    DIRECTION INPUT ;
    USE SIGNAL ;
    ANTENNAGATEAREA 0.213000 ;
    PORT
      LAYER met2 ;
        RECT 105.430 259.480 105.710 259.760 ;
    END
  END S4END[11]
  PIN S4END[12]
    DIRECTION INPUT ;
    USE SIGNAL ;
    ANTENNAGATEAREA 0.682200 ;
    ANTENNADIFFAREA 0.434700 ;
    PORT
      LAYER met2 ;
        RECT 106.350 259.480 106.630 259.760 ;
    END
  END S4END[12]
  PIN S4END[13]
    DIRECTION INPUT ;
    USE SIGNAL ;
    ANTENNAGATEAREA 0.247500 ;
    PORT
      LAYER met2 ;
        RECT 107.270 259.480 107.550 259.760 ;
    END
  END S4END[13]
  PIN S4END[14]
    DIRECTION INPUT ;
    USE SIGNAL ;
    ANTENNAGATEAREA 0.247500 ;
    PORT
      LAYER met2 ;
        RECT 108.190 259.480 108.470 259.760 ;
    END
  END S4END[14]
  PIN S4END[15]
    DIRECTION INPUT ;
    USE SIGNAL ;
    ANTENNAGATEAREA 0.247500 ;
    PORT
      LAYER met2 ;
        RECT 109.110 259.480 109.390 259.760 ;
    END
  END S4END[15]
  PIN S4END[1]
    DIRECTION INPUT ;
    USE SIGNAL ;
    ANTENNAGATEAREA 0.696000 ;
    PORT
      LAYER met2 ;
        RECT 96.230 259.480 96.510 259.760 ;
    END
  END S4END[1]
  PIN S4END[2]
    DIRECTION INPUT ;
    USE SIGNAL ;
    ANTENNAGATEAREA 0.663000 ;
    PORT
      LAYER met2 ;
        RECT 97.150 259.480 97.430 259.760 ;
    END
  END S4END[2]
  PIN S4END[3]
    DIRECTION INPUT ;
    USE SIGNAL ;
    ANTENNAGATEAREA 1.097700 ;
    ANTENNADIFFAREA 0.434700 ;
    PORT
      LAYER met2 ;
        RECT 98.070 259.480 98.350 259.760 ;
    END
  END S4END[3]
  PIN S4END[4]
    DIRECTION INPUT ;
    USE SIGNAL ;
    ANTENNAGATEAREA 0.247500 ;
    PORT
      LAYER met2 ;
        RECT 98.990 259.480 99.270 259.760 ;
    END
  END S4END[4]
  PIN S4END[5]
    DIRECTION INPUT ;
    USE SIGNAL ;
    ANTENNAGATEAREA 0.247500 ;
    PORT
      LAYER met2 ;
        RECT 99.910 259.480 100.190 259.760 ;
    END
  END S4END[5]
  PIN S4END[6]
    DIRECTION INPUT ;
    USE SIGNAL ;
    ANTENNAGATEAREA 0.682200 ;
    ANTENNADIFFAREA 0.434700 ;
    PORT
      LAYER met2 ;
        RECT 100.830 259.480 101.110 259.760 ;
    END
  END S4END[6]
  PIN S4END[7]
    DIRECTION INPUT ;
    USE SIGNAL ;
    ANTENNAGATEAREA 0.682200 ;
    ANTENNADIFFAREA 0.434700 ;
    PORT
      LAYER met2 ;
        RECT 101.750 259.480 102.030 259.760 ;
    END
  END S4END[7]
  PIN S4END[8]
    DIRECTION INPUT ;
    USE SIGNAL ;
    ANTENNAGATEAREA 0.247500 ;
    PORT
      LAYER met2 ;
        RECT 102.670 259.480 102.950 259.760 ;
    END
  END S4END[8]
  PIN S4END[9]
    DIRECTION INPUT ;
    USE SIGNAL ;
    ANTENNAGATEAREA 0.247500 ;
    PORT
      LAYER met2 ;
        RECT 103.590 259.480 103.870 259.760 ;
    END
  END S4END[9]
  PIN SS4BEG[0]
    DIRECTION OUTPUT ;
    USE SIGNAL ;
    ANTENNADIFFAREA 0.445500 ;
    PORT
      LAYER met2 ;
        RECT 110.030 0.000 110.310 0.280 ;
    END
  END SS4BEG[0]
  PIN SS4BEG[10]
    DIRECTION OUTPUT ;
    USE SIGNAL ;
    ANTENNADIFFAREA 0.445500 ;
    PORT
      LAYER met2 ;
        RECT 119.230 0.000 119.510 0.280 ;
    END
  END SS4BEG[10]
  PIN SS4BEG[11]
    DIRECTION OUTPUT ;
    USE SIGNAL ;
    ANTENNADIFFAREA 0.445500 ;
    PORT
      LAYER met2 ;
        RECT 120.150 0.000 120.430 0.280 ;
    END
  END SS4BEG[11]
  PIN SS4BEG[12]
    DIRECTION OUTPUT ;
    USE SIGNAL ;
    ANTENNADIFFAREA 0.891000 ;
    PORT
      LAYER met2 ;
        RECT 121.070 0.000 121.350 0.280 ;
    END
  END SS4BEG[12]
  PIN SS4BEG[13]
    DIRECTION OUTPUT ;
    USE SIGNAL ;
    ANTENNADIFFAREA 1.782000 ;
    PORT
      LAYER met2 ;
        RECT 121.990 0.000 122.270 0.280 ;
    END
  END SS4BEG[13]
  PIN SS4BEG[14]
    DIRECTION OUTPUT ;
    USE SIGNAL ;
    ANTENNADIFFAREA 1.336500 ;
    PORT
      LAYER met2 ;
        RECT 122.910 0.000 123.190 0.280 ;
    END
  END SS4BEG[14]
  PIN SS4BEG[15]
    DIRECTION OUTPUT ;
    USE SIGNAL ;
    ANTENNADIFFAREA 1.336500 ;
    PORT
      LAYER met2 ;
        RECT 123.830 0.000 124.110 0.280 ;
    END
  END SS4BEG[15]
  PIN SS4BEG[1]
    DIRECTION OUTPUT ;
    USE SIGNAL ;
    ANTENNADIFFAREA 0.445500 ;
    PORT
      LAYER met2 ;
        RECT 110.950 0.000 111.230 0.280 ;
    END
  END SS4BEG[1]
  PIN SS4BEG[2]
    DIRECTION OUTPUT ;
    USE SIGNAL ;
    ANTENNADIFFAREA 0.445500 ;
    PORT
      LAYER met2 ;
        RECT 111.870 0.000 112.150 0.280 ;
    END
  END SS4BEG[2]
  PIN SS4BEG[3]
    DIRECTION OUTPUT ;
    USE SIGNAL ;
    ANTENNADIFFAREA 0.445500 ;
    PORT
      LAYER met2 ;
        RECT 112.790 0.000 113.070 0.280 ;
    END
  END SS4BEG[3]
  PIN SS4BEG[4]
    DIRECTION OUTPUT ;
    USE SIGNAL ;
    ANTENNADIFFAREA 0.445500 ;
    PORT
      LAYER met2 ;
        RECT 113.710 0.000 113.990 0.280 ;
    END
  END SS4BEG[4]
  PIN SS4BEG[5]
    DIRECTION OUTPUT ;
    USE SIGNAL ;
    ANTENNADIFFAREA 0.445500 ;
    PORT
      LAYER met2 ;
        RECT 114.630 0.000 114.910 0.280 ;
    END
  END SS4BEG[5]
  PIN SS4BEG[6]
    DIRECTION OUTPUT ;
    USE SIGNAL ;
    ANTENNADIFFAREA 0.445500 ;
    PORT
      LAYER met2 ;
        RECT 115.550 0.000 115.830 0.280 ;
    END
  END SS4BEG[6]
  PIN SS4BEG[7]
    DIRECTION OUTPUT ;
    USE SIGNAL ;
    ANTENNADIFFAREA 0.445500 ;
    PORT
      LAYER met2 ;
        RECT 116.470 0.000 116.750 0.280 ;
    END
  END SS4BEG[7]
  PIN SS4BEG[8]
    DIRECTION OUTPUT ;
    USE SIGNAL ;
    ANTENNADIFFAREA 0.445500 ;
    PORT
      LAYER met2 ;
        RECT 117.390 0.000 117.670 0.280 ;
    END
  END SS4BEG[8]
  PIN SS4BEG[9]
    DIRECTION OUTPUT ;
    USE SIGNAL ;
    ANTENNADIFFAREA 0.445500 ;
    PORT
      LAYER met2 ;
        RECT 118.310 0.000 118.590 0.280 ;
    END
  END SS4BEG[9]
  PIN SS4END[0]
    DIRECTION INPUT ;
    USE SIGNAL ;
    ANTENNAGATEAREA 1.715100 ;
    ANTENNADIFFAREA 1.304100 ;
    PORT
      LAYER met2 ;
        RECT 110.030 259.480 110.310 259.760 ;
    END
  END SS4END[0]
  PIN SS4END[10]
    DIRECTION INPUT ;
    USE SIGNAL ;
    ANTENNAGATEAREA 0.159000 ;
    PORT
      LAYER met2 ;
        RECT 119.230 259.480 119.510 259.760 ;
    END
  END SS4END[10]
  PIN SS4END[11]
    DIRECTION INPUT ;
    USE SIGNAL ;
    ANTENNAGATEAREA 0.213000 ;
    PORT
      LAYER met2 ;
        RECT 120.150 259.480 120.430 259.760 ;
    END
  END SS4END[11]
  PIN SS4END[12]
    DIRECTION INPUT ;
    USE SIGNAL ;
    ANTENNAGATEAREA 0.213000 ;
    PORT
      LAYER met2 ;
        RECT 121.070 259.480 121.350 259.760 ;
    END
  END SS4END[12]
  PIN SS4END[13]
    DIRECTION INPUT ;
    USE SIGNAL ;
    ANTENNAGATEAREA 0.213000 ;
    PORT
      LAYER met2 ;
        RECT 121.990 259.480 122.270 259.760 ;
    END
  END SS4END[13]
  PIN SS4END[14]
    DIRECTION INPUT ;
    USE SIGNAL ;
    ANTENNAGATEAREA 0.213000 ;
    PORT
      LAYER met2 ;
        RECT 122.910 259.480 123.190 259.760 ;
    END
  END SS4END[14]
  PIN SS4END[15]
    DIRECTION INPUT ;
    USE SIGNAL ;
    ANTENNAGATEAREA 0.213000 ;
    PORT
      LAYER met2 ;
        RECT 123.830 259.480 124.110 259.760 ;
    END
  END SS4END[15]
  PIN SS4END[1]
    DIRECTION INPUT ;
    USE SIGNAL ;
    ANTENNAGATEAREA 2.182800 ;
    ANTENNADIFFAREA 1.738800 ;
    PORT
      LAYER met2 ;
        RECT 110.950 259.480 111.230 259.760 ;
    END
  END SS4END[1]
  PIN SS4END[2]
    DIRECTION INPUT ;
    USE SIGNAL ;
    ANTENNAGATEAREA 1.313400 ;
    ANTENNADIFFAREA 0.869400 ;
    PORT
      LAYER met2 ;
        RECT 111.870 259.480 112.150 259.760 ;
    END
  END SS4END[2]
  PIN SS4END[3]
    DIRECTION INPUT ;
    USE SIGNAL ;
    ANTENNAGATEAREA 0.444000 ;
    PORT
      LAYER met2 ;
        RECT 112.790 259.480 113.070 259.760 ;
    END
  END SS4END[3]
  PIN SS4END[4]
    DIRECTION INPUT ;
    USE SIGNAL ;
    ANTENNAGATEAREA 0.247500 ;
    PORT
      LAYER met2 ;
        RECT 113.710 259.480 113.990 259.760 ;
    END
  END SS4END[4]
  PIN SS4END[5]
    DIRECTION INPUT ;
    USE SIGNAL ;
    ANTENNAGATEAREA 0.159000 ;
    PORT
      LAYER met2 ;
        RECT 114.630 259.480 114.910 259.760 ;
    END
  END SS4END[5]
  PIN SS4END[6]
    DIRECTION INPUT ;
    USE SIGNAL ;
    ANTENNAGATEAREA 0.247500 ;
    PORT
      LAYER met2 ;
        RECT 115.550 259.480 115.830 259.760 ;
    END
  END SS4END[6]
  PIN SS4END[7]
    DIRECTION INPUT ;
    USE SIGNAL ;
    ANTENNAGATEAREA 0.247500 ;
    PORT
      LAYER met2 ;
        RECT 116.470 259.480 116.750 259.760 ;
    END
  END SS4END[7]
  PIN SS4END[8]
    DIRECTION INPUT ;
    USE SIGNAL ;
    ANTENNAGATEAREA 0.159000 ;
    PORT
      LAYER met2 ;
        RECT 117.390 259.480 117.670 259.760 ;
    END
  END SS4END[8]
  PIN SS4END[9]
    DIRECTION INPUT ;
    USE SIGNAL ;
    ANTENNAGATEAREA 0.159000 ;
    PORT
      LAYER met2 ;
        RECT 118.310 259.480 118.590 259.760 ;
    END
  END SS4END[9]
  PIN UserCLK
    DIRECTION INPUT ;
    USE SIGNAL ;
    ANTENNAGATEAREA 1.704000 ;
    PORT
      LAYER met2 ;
        RECT 124.750 0.000 125.030 0.280 ;
    END
  END UserCLK
  PIN UserCLKo
    DIRECTION OUTPUT ;
    USE SIGNAL ;
    ANTENNADIFFAREA 0.340600 ;
    PORT
      LAYER met2 ;
        RECT 124.750 259.480 125.030 259.760 ;
    END
  END UserCLKo
  PIN VGND
    DIRECTION INOUT ;
    USE GROUND ;
    PORT
      LAYER met4 ;
        RECT 15.020 0.000 16.620 259.760 ;
    END
    PORT
      LAYER met4 ;
        RECT 45.020 0.000 46.620 259.760 ;
    END
    PORT
      LAYER met4 ;
        RECT 75.020 0.000 76.620 259.760 ;
    END
    PORT
      LAYER met4 ;
        RECT 105.020 0.000 106.620 259.760 ;
    END
    PORT
      LAYER met4 ;
        RECT 135.020 0.000 136.620 259.760 ;
    END
    PORT
      LAYER met4 ;
        RECT 165.020 0.000 166.620 259.760 ;
    END
  END VGND
  PIN VPWR
    DIRECTION INOUT ;
    USE POWER ;
    PORT
      LAYER met4 ;
        RECT 9.720 0.000 11.320 259.760 ;
    END
    PORT
      LAYER met4 ;
        RECT 39.720 0.000 41.320 259.760 ;
    END
    PORT
      LAYER met4 ;
        RECT 69.720 0.000 71.320 259.760 ;
    END
    PORT
      LAYER met4 ;
        RECT 99.720 0.000 101.320 259.760 ;
    END
    PORT
      LAYER met4 ;
        RECT 129.720 0.000 131.320 259.760 ;
    END
    PORT
      LAYER met4 ;
        RECT 159.720 0.000 161.320 259.760 ;
    END
  END VPWR
  PIN W1BEG[0]
    DIRECTION OUTPUT ;
    USE SIGNAL ;
    ANTENNADIFFAREA 0.891000 ;
    PORT
      LAYER met3 ;
        RECT 0.000 42.200 0.600 42.800 ;
    END
  END W1BEG[0]
  PIN W1BEG[1]
    DIRECTION OUTPUT ;
    USE SIGNAL ;
    ANTENNADIFFAREA 0.891000 ;
    PORT
      LAYER met3 ;
        RECT 0.000 43.560 0.600 44.160 ;
    END
  END W1BEG[1]
  PIN W1BEG[2]
    DIRECTION OUTPUT ;
    USE SIGNAL ;
    ANTENNADIFFAREA 1.336500 ;
    PORT
      LAYER met3 ;
        RECT 0.000 44.920 0.600 45.520 ;
    END
  END W1BEG[2]
  PIN W1BEG[3]
    DIRECTION OUTPUT ;
    USE SIGNAL ;
    ANTENNADIFFAREA 0.891000 ;
    PORT
      LAYER met3 ;
        RECT 0.000 46.280 0.600 46.880 ;
    END
  END W1BEG[3]
  PIN W1END[0]
    DIRECTION INPUT ;
    USE SIGNAL ;
    ANTENNAGATEAREA 1.008000 ;
    PORT
      LAYER met3 ;
        RECT 171.440 42.200 172.040 42.800 ;
    END
  END W1END[0]
  PIN W1END[1]
    DIRECTION INPUT ;
    USE SIGNAL ;
    ANTENNAGATEAREA 1.134000 ;
    PORT
      LAYER met3 ;
        RECT 171.440 43.560 172.040 44.160 ;
    END
  END W1END[1]
  PIN W1END[2]
    DIRECTION INPUT ;
    USE SIGNAL ;
    ANTENNAGATEAREA 0.339000 ;
    PORT
      LAYER met3 ;
        RECT 171.440 44.920 172.040 45.520 ;
    END
  END W1END[2]
  PIN W1END[3]
    DIRECTION INPUT ;
    USE SIGNAL ;
    ANTENNAGATEAREA 1.208400 ;
    ANTENNADIFFAREA 0.869400 ;
    PORT
      LAYER met3 ;
        RECT 171.440 46.280 172.040 46.880 ;
    END
  END W1END[3]
  PIN W2BEG[0]
    DIRECTION OUTPUT ;
    USE SIGNAL ;
    ANTENNADIFFAREA 0.891000 ;
    PORT
      LAYER met3 ;
        RECT 0.000 47.640 0.600 48.240 ;
    END
  END W2BEG[0]
  PIN W2BEG[1]
    DIRECTION OUTPUT ;
    USE SIGNAL ;
    ANTENNADIFFAREA 0.795200 ;
    PORT
      LAYER met3 ;
        RECT 0.000 49.000 0.600 49.600 ;
    END
  END W2BEG[1]
  PIN W2BEG[2]
    DIRECTION OUTPUT ;
    USE SIGNAL ;
    ANTENNADIFFAREA 1.336500 ;
    PORT
      LAYER met3 ;
        RECT 0.000 50.360 0.600 50.960 ;
    END
  END W2BEG[2]
  PIN W2BEG[3]
    DIRECTION OUTPUT ;
    USE SIGNAL ;
    ANTENNADIFFAREA 0.795200 ;
    PORT
      LAYER met3 ;
        RECT 0.000 51.720 0.600 52.320 ;
    END
  END W2BEG[3]
  PIN W2BEG[4]
    DIRECTION OUTPUT ;
    USE SIGNAL ;
    ANTENNADIFFAREA 1.782000 ;
    PORT
      LAYER met3 ;
        RECT 0.000 53.080 0.600 53.680 ;
    END
  END W2BEG[4]
  PIN W2BEG[5]
    DIRECTION OUTPUT ;
    USE SIGNAL ;
    ANTENNADIFFAREA 1.336500 ;
    PORT
      LAYER met3 ;
        RECT 0.000 54.440 0.600 55.040 ;
    END
  END W2BEG[5]
  PIN W2BEG[6]
    DIRECTION OUTPUT ;
    USE SIGNAL ;
    ANTENNADIFFAREA 1.336500 ;
    PORT
      LAYER met3 ;
        RECT 0.000 55.800 0.600 56.400 ;
    END
  END W2BEG[6]
  PIN W2BEG[7]
    DIRECTION OUTPUT ;
    USE SIGNAL ;
    ANTENNADIFFAREA 0.795200 ;
    PORT
      LAYER met3 ;
        RECT 0.000 57.160 0.600 57.760 ;
    END
  END W2BEG[7]
  PIN W2BEGb[0]
    DIRECTION OUTPUT ;
    USE SIGNAL ;
    ANTENNADIFFAREA 0.445500 ;
    PORT
      LAYER met3 ;
        RECT 0.000 58.520 0.600 59.120 ;
    END
  END W2BEGb[0]
  PIN W2BEGb[1]
    DIRECTION OUTPUT ;
    USE SIGNAL ;
    ANTENNADIFFAREA 0.445500 ;
    PORT
      LAYER met3 ;
        RECT 0.000 59.880 0.600 60.480 ;
    END
  END W2BEGb[1]
  PIN W2BEGb[2]
    DIRECTION OUTPUT ;
    USE SIGNAL ;
    ANTENNADIFFAREA 0.445500 ;
    PORT
      LAYER met3 ;
        RECT 0.000 61.240 0.600 61.840 ;
    END
  END W2BEGb[2]
  PIN W2BEGb[3]
    DIRECTION OUTPUT ;
    USE SIGNAL ;
    ANTENNADIFFAREA 0.445500 ;
    PORT
      LAYER met3 ;
        RECT 0.000 62.600 0.600 63.200 ;
    END
  END W2BEGb[3]
  PIN W2BEGb[4]
    DIRECTION OUTPUT ;
    USE SIGNAL ;
    ANTENNADIFFAREA 0.445500 ;
    PORT
      LAYER met3 ;
        RECT 0.000 63.960 0.600 64.560 ;
    END
  END W2BEGb[4]
  PIN W2BEGb[5]
    DIRECTION OUTPUT ;
    USE SIGNAL ;
    ANTENNADIFFAREA 0.445500 ;
    PORT
      LAYER met3 ;
        RECT 0.000 65.320 0.600 65.920 ;
    END
  END W2BEGb[5]
  PIN W2BEGb[6]
    DIRECTION OUTPUT ;
    USE SIGNAL ;
    ANTENNADIFFAREA 0.445500 ;
    PORT
      LAYER met3 ;
        RECT 0.000 66.680 0.600 67.280 ;
    END
  END W2BEGb[6]
  PIN W2BEGb[7]
    DIRECTION OUTPUT ;
    USE SIGNAL ;
    ANTENNADIFFAREA 0.445500 ;
    PORT
      LAYER met3 ;
        RECT 0.000 68.040 0.600 68.640 ;
    END
  END W2BEGb[7]
  PIN W2END[0]
    DIRECTION INPUT ;
    USE SIGNAL ;
    ANTENNAGATEAREA 2.560800 ;
    ANTENNADIFFAREA 1.738800 ;
    PORT
      LAYER met3 ;
        RECT 171.440 58.520 172.040 59.120 ;
    END
  END W2END[0]
  PIN W2END[1]
    DIRECTION INPUT ;
    USE SIGNAL ;
    ANTENNAGATEAREA 0.822000 ;
    PORT
      LAYER met3 ;
        RECT 171.440 59.880 172.040 60.480 ;
    END
  END W2END[1]
  PIN W2END[2]
    DIRECTION INPUT ;
    USE SIGNAL ;
    ANTENNAGATEAREA 2.126100 ;
    ANTENNADIFFAREA 1.304100 ;
    PORT
      LAYER met3 ;
        RECT 171.440 61.240 172.040 61.840 ;
    END
  END W2END[2]
  PIN W2END[3]
    DIRECTION INPUT ;
    USE SIGNAL ;
    ANTENNAGATEAREA 0.789000 ;
    PORT
      LAYER met3 ;
        RECT 171.440 62.600 172.040 63.200 ;
    END
  END W2END[3]
  PIN W2END[4]
    DIRECTION INPUT ;
    USE SIGNAL ;
    ANTENNAGATEAREA 0.981000 ;
    PORT
      LAYER met3 ;
        RECT 171.440 63.960 172.040 64.560 ;
    END
  END W2END[4]
  PIN W2END[5]
    DIRECTION INPUT ;
    USE SIGNAL ;
    ANTENNAGATEAREA 0.822000 ;
    PORT
      LAYER met3 ;
        RECT 171.440 65.320 172.040 65.920 ;
    END
  END W2END[5]
  PIN W2END[6]
    DIRECTION INPUT ;
    USE SIGNAL ;
    ANTENNAGATEAREA 3.430200 ;
    ANTENNADIFFAREA 2.608200 ;
    PORT
      LAYER met3 ;
        RECT 171.440 66.680 172.040 67.280 ;
    END
  END W2END[6]
  PIN W2END[7]
    DIRECTION INPUT ;
    USE SIGNAL ;
    ANTENNAGATEAREA 2.318100 ;
    ANTENNADIFFAREA 1.304100 ;
    PORT
      LAYER met3 ;
        RECT 171.440 68.040 172.040 68.640 ;
    END
  END W2END[7]
  PIN W2MID[0]
    DIRECTION INPUT ;
    USE SIGNAL ;
    ANTENNAGATEAREA 0.673500 ;
    PORT
      LAYER met3 ;
        RECT 171.440 47.640 172.040 48.240 ;
    END
  END W2MID[0]
  PIN W2MID[1]
    DIRECTION INPUT ;
    USE SIGNAL ;
    ANTENNAGATEAREA 0.799500 ;
    PORT
      LAYER met3 ;
        RECT 171.440 49.000 172.040 49.600 ;
    END
  END W2MID[1]
  PIN W2MID[2]
    DIRECTION INPUT ;
    USE SIGNAL ;
    ANTENNAGATEAREA 0.691500 ;
    PORT
      LAYER met3 ;
        RECT 171.440 50.360 172.040 50.960 ;
    END
  END W2MID[2]
  PIN W2MID[3]
    DIRECTION INPUT ;
    USE SIGNAL ;
    ANTENNAGATEAREA 0.832500 ;
    PORT
      LAYER met3 ;
        RECT 171.440 51.720 172.040 52.320 ;
    END
  END W2MID[3]
  PIN W2MID[4]
    DIRECTION INPUT ;
    USE SIGNAL ;
    ANTENNAGATEAREA 1.080000 ;
    PORT
      LAYER met3 ;
        RECT 171.440 53.080 172.040 53.680 ;
    END
  END W2MID[4]
  PIN W2MID[5]
    DIRECTION INPUT ;
    USE SIGNAL ;
    ANTENNAGATEAREA 0.750000 ;
    PORT
      LAYER met3 ;
        RECT 171.440 54.440 172.040 55.040 ;
    END
  END W2MID[5]
  PIN W2MID[6]
    DIRECTION INPUT ;
    USE SIGNAL ;
    ANTENNAGATEAREA 0.607500 ;
    PORT
      LAYER met3 ;
        RECT 171.440 55.800 172.040 56.400 ;
    END
  END W2MID[6]
  PIN W2MID[7]
    DIRECTION INPUT ;
    USE SIGNAL ;
    ANTENNAGATEAREA 0.783000 ;
    PORT
      LAYER met3 ;
        RECT 171.440 57.160 172.040 57.760 ;
    END
  END W2MID[7]
  PIN W6BEG[0]
    DIRECTION OUTPUT ;
    USE SIGNAL ;
    ANTENNADIFFAREA 0.445500 ;
    PORT
      LAYER met3 ;
        RECT 0.000 91.160 0.600 91.760 ;
    END
  END W6BEG[0]
  PIN W6BEG[10]
    DIRECTION OUTPUT ;
    USE SIGNAL ;
    ANTENNADIFFAREA 0.891000 ;
    PORT
      LAYER met3 ;
        RECT 0.000 104.760 0.600 105.360 ;
    END
  END W6BEG[10]
  PIN W6BEG[11]
    DIRECTION OUTPUT ;
    USE SIGNAL ;
    ANTENNADIFFAREA 1.336500 ;
    PORT
      LAYER met3 ;
        RECT 0.000 106.120 0.600 106.720 ;
    END
  END W6BEG[11]
  PIN W6BEG[1]
    DIRECTION OUTPUT ;
    USE SIGNAL ;
    ANTENNADIFFAREA 0.445500 ;
    PORT
      LAYER met3 ;
        RECT 0.000 92.520 0.600 93.120 ;
    END
  END W6BEG[1]
  PIN W6BEG[2]
    DIRECTION OUTPUT ;
    USE SIGNAL ;
    ANTENNADIFFAREA 0.445500 ;
    PORT
      LAYER met3 ;
        RECT 0.000 93.880 0.600 94.480 ;
    END
  END W6BEG[2]
  PIN W6BEG[3]
    DIRECTION OUTPUT ;
    USE SIGNAL ;
    ANTENNADIFFAREA 0.445500 ;
    PORT
      LAYER met3 ;
        RECT 0.000 95.240 0.600 95.840 ;
    END
  END W6BEG[3]
  PIN W6BEG[4]
    DIRECTION OUTPUT ;
    USE SIGNAL ;
    ANTENNADIFFAREA 0.445500 ;
    PORT
      LAYER met3 ;
        RECT 0.000 96.600 0.600 97.200 ;
    END
  END W6BEG[4]
  PIN W6BEG[5]
    DIRECTION OUTPUT ;
    USE SIGNAL ;
    ANTENNADIFFAREA 0.445500 ;
    PORT
      LAYER met3 ;
        RECT 0.000 97.960 0.600 98.560 ;
    END
  END W6BEG[5]
  PIN W6BEG[6]
    DIRECTION OUTPUT ;
    USE SIGNAL ;
    ANTENNADIFFAREA 0.445500 ;
    PORT
      LAYER met3 ;
        RECT 0.000 99.320 0.600 99.920 ;
    END
  END W6BEG[6]
  PIN W6BEG[7]
    DIRECTION OUTPUT ;
    USE SIGNAL ;
    ANTENNADIFFAREA 0.445500 ;
    PORT
      LAYER met3 ;
        RECT 0.000 100.680 0.600 101.280 ;
    END
  END W6BEG[7]
  PIN W6BEG[8]
    DIRECTION OUTPUT ;
    USE SIGNAL ;
    ANTENNADIFFAREA 0.445500 ;
    PORT
      LAYER met3 ;
        RECT 0.000 102.040 0.600 102.640 ;
    END
  END W6BEG[8]
  PIN W6BEG[9]
    DIRECTION OUTPUT ;
    USE SIGNAL ;
    ANTENNADIFFAREA 0.445500 ;
    PORT
      LAYER met3 ;
        RECT 0.000 103.400 0.600 104.000 ;
    END
  END W6BEG[9]
  PIN W6END[0]
    DIRECTION INPUT ;
    USE SIGNAL ;
    ANTENNAGATEAREA 1.107000 ;
    PORT
      LAYER met3 ;
        RECT 171.440 91.160 172.040 91.760 ;
    END
  END W6END[0]
  PIN W6END[10]
    DIRECTION INPUT ;
    USE SIGNAL ;
    ANTENNAGATEAREA 0.213000 ;
    PORT
      LAYER met3 ;
        RECT 171.440 104.760 172.040 105.360 ;
    END
  END W6END[10]
  PIN W6END[11]
    DIRECTION INPUT ;
    USE SIGNAL ;
    ANTENNAGATEAREA 0.213000 ;
    PORT
      LAYER met3 ;
        RECT 171.440 106.120 172.040 106.720 ;
    END
  END W6END[11]
  PIN W6END[1]
    DIRECTION INPUT ;
    USE SIGNAL ;
    ANTENNAGATEAREA 4.401900 ;
    ANTENNADIFFAREA 3.042900 ;
    PORT
      LAYER met3 ;
        RECT 171.440 92.520 172.040 93.120 ;
    END
  END W6END[1]
  PIN W6END[2]
    DIRECTION INPUT ;
    USE SIGNAL ;
    ANTENNAGATEAREA 0.213000 ;
    PORT
      LAYER met3 ;
        RECT 171.440 93.880 172.040 94.480 ;
    END
  END W6END[2]
  PIN W6END[3]
    DIRECTION INPUT ;
    USE SIGNAL ;
    ANTENNAGATEAREA 0.213000 ;
    PORT
      LAYER met3 ;
        RECT 171.440 95.240 172.040 95.840 ;
    END
  END W6END[3]
  PIN W6END[4]
    DIRECTION INPUT ;
    USE SIGNAL ;
    ANTENNAGATEAREA 0.213000 ;
    PORT
      LAYER met3 ;
        RECT 171.440 96.600 172.040 97.200 ;
    END
  END W6END[4]
  PIN W6END[5]
    DIRECTION INPUT ;
    USE SIGNAL ;
    ANTENNAGATEAREA 0.213000 ;
    PORT
      LAYER met3 ;
        RECT 171.440 97.960 172.040 98.560 ;
    END
  END W6END[5]
  PIN W6END[6]
    DIRECTION INPUT ;
    USE SIGNAL ;
    ANTENNAGATEAREA 0.213000 ;
    PORT
      LAYER met3 ;
        RECT 171.440 99.320 172.040 99.920 ;
    END
  END W6END[6]
  PIN W6END[7]
    DIRECTION INPUT ;
    USE SIGNAL ;
    ANTENNAGATEAREA 0.213000 ;
    PORT
      LAYER met3 ;
        RECT 171.440 100.680 172.040 101.280 ;
    END
  END W6END[7]
  PIN W6END[8]
    DIRECTION INPUT ;
    USE SIGNAL ;
    ANTENNAGATEAREA 0.213000 ;
    PORT
      LAYER met3 ;
        RECT 171.440 102.040 172.040 102.640 ;
    END
  END W6END[8]
  PIN W6END[9]
    DIRECTION INPUT ;
    USE SIGNAL ;
    ANTENNAGATEAREA 0.213000 ;
    PORT
      LAYER met3 ;
        RECT 171.440 103.400 172.040 104.000 ;
    END
  END W6END[9]
  PIN WW4BEG[0]
    DIRECTION OUTPUT ;
    USE SIGNAL ;
    ANTENNADIFFAREA 0.445500 ;
    PORT
      LAYER met3 ;
        RECT 0.000 69.400 0.600 70.000 ;
    END
  END WW4BEG[0]
  PIN WW4BEG[10]
    DIRECTION OUTPUT ;
    USE SIGNAL ;
    ANTENNADIFFAREA 0.445500 ;
    PORT
      LAYER met3 ;
        RECT 0.000 83.000 0.600 83.600 ;
    END
  END WW4BEG[10]
  PIN WW4BEG[11]
    DIRECTION OUTPUT ;
    USE SIGNAL ;
    ANTENNADIFFAREA 0.445500 ;
    PORT
      LAYER met3 ;
        RECT 0.000 84.360 0.600 84.960 ;
    END
  END WW4BEG[11]
  PIN WW4BEG[12]
    DIRECTION OUTPUT ;
    USE SIGNAL ;
    ANTENNADIFFAREA 0.891000 ;
    PORT
      LAYER met3 ;
        RECT 0.000 85.720 0.600 86.320 ;
    END
  END WW4BEG[12]
  PIN WW4BEG[13]
    DIRECTION OUTPUT ;
    USE SIGNAL ;
    ANTENNADIFFAREA 1.782000 ;
    PORT
      LAYER met3 ;
        RECT 0.000 87.080 0.600 87.680 ;
    END
  END WW4BEG[13]
  PIN WW4BEG[14]
    DIRECTION OUTPUT ;
    USE SIGNAL ;
    ANTENNADIFFAREA 0.891000 ;
    PORT
      LAYER met3 ;
        RECT 0.000 88.440 0.600 89.040 ;
    END
  END WW4BEG[14]
  PIN WW4BEG[15]
    DIRECTION OUTPUT ;
    USE SIGNAL ;
    ANTENNADIFFAREA 1.782000 ;
    PORT
      LAYER met3 ;
        RECT 0.000 89.800 0.600 90.400 ;
    END
  END WW4BEG[15]
  PIN WW4BEG[1]
    DIRECTION OUTPUT ;
    USE SIGNAL ;
    ANTENNADIFFAREA 0.445500 ;
    PORT
      LAYER met3 ;
        RECT 0.000 70.760 0.600 71.360 ;
    END
  END WW4BEG[1]
  PIN WW4BEG[2]
    DIRECTION OUTPUT ;
    USE SIGNAL ;
    ANTENNADIFFAREA 0.445500 ;
    PORT
      LAYER met3 ;
        RECT 0.000 72.120 0.600 72.720 ;
    END
  END WW4BEG[2]
  PIN WW4BEG[3]
    DIRECTION OUTPUT ;
    USE SIGNAL ;
    ANTENNADIFFAREA 0.445500 ;
    PORT
      LAYER met3 ;
        RECT 0.000 73.480 0.600 74.080 ;
    END
  END WW4BEG[3]
  PIN WW4BEG[4]
    DIRECTION OUTPUT ;
    USE SIGNAL ;
    ANTENNADIFFAREA 0.445500 ;
    PORT
      LAYER met3 ;
        RECT 0.000 74.840 0.600 75.440 ;
    END
  END WW4BEG[4]
  PIN WW4BEG[5]
    DIRECTION OUTPUT ;
    USE SIGNAL ;
    ANTENNADIFFAREA 0.445500 ;
    PORT
      LAYER met3 ;
        RECT 0.000 76.200 0.600 76.800 ;
    END
  END WW4BEG[5]
  PIN WW4BEG[6]
    DIRECTION OUTPUT ;
    USE SIGNAL ;
    ANTENNADIFFAREA 0.445500 ;
    PORT
      LAYER met3 ;
        RECT 0.000 77.560 0.600 78.160 ;
    END
  END WW4BEG[6]
  PIN WW4BEG[7]
    DIRECTION OUTPUT ;
    USE SIGNAL ;
    ANTENNADIFFAREA 0.445500 ;
    PORT
      LAYER met3 ;
        RECT 0.000 78.920 0.600 79.520 ;
    END
  END WW4BEG[7]
  PIN WW4BEG[8]
    DIRECTION OUTPUT ;
    USE SIGNAL ;
    ANTENNADIFFAREA 0.445500 ;
    PORT
      LAYER met3 ;
        RECT 0.000 80.280 0.600 80.880 ;
    END
  END WW4BEG[8]
  PIN WW4BEG[9]
    DIRECTION OUTPUT ;
    USE SIGNAL ;
    ANTENNADIFFAREA 0.445500 ;
    PORT
      LAYER met3 ;
        RECT 0.000 81.640 0.600 82.240 ;
    END
  END WW4BEG[9]
  PIN WW4END[0]
    DIRECTION INPUT ;
    USE SIGNAL ;
    ANTENNAGATEAREA 2.617500 ;
    ANTENNADIFFAREA 2.173500 ;
    PORT
      LAYER met3 ;
        RECT 171.440 69.400 172.040 70.000 ;
    END
  END WW4END[0]
  PIN WW4END[10]
    DIRECTION INPUT ;
    USE SIGNAL ;
    ANTENNAGATEAREA 0.213000 ;
    PORT
      LAYER met3 ;
        RECT 171.440 83.000 172.040 83.600 ;
    END
  END WW4END[10]
  PIN WW4END[11]
    DIRECTION INPUT ;
    USE SIGNAL ;
    ANTENNAGATEAREA 0.213000 ;
    PORT
      LAYER met3 ;
        RECT 171.440 84.360 172.040 84.960 ;
    END
  END WW4END[11]
  PIN WW4END[12]
    DIRECTION INPUT ;
    USE SIGNAL ;
    ANTENNAGATEAREA 0.213000 ;
    PORT
      LAYER met3 ;
        RECT 171.440 85.720 172.040 86.320 ;
    END
  END WW4END[12]
  PIN WW4END[13]
    DIRECTION INPUT ;
    USE SIGNAL ;
    ANTENNAGATEAREA 0.213000 ;
    PORT
      LAYER met3 ;
        RECT 171.440 87.080 172.040 87.680 ;
    END
  END WW4END[13]
  PIN WW4END[14]
    DIRECTION INPUT ;
    USE SIGNAL ;
    ANTENNAGATEAREA 0.213000 ;
    PORT
      LAYER met3 ;
        RECT 171.440 88.440 172.040 89.040 ;
    END
  END WW4END[14]
  PIN WW4END[15]
    DIRECTION INPUT ;
    USE SIGNAL ;
    ANTENNAGATEAREA 0.213000 ;
    PORT
      LAYER met3 ;
        RECT 171.440 89.800 172.040 90.400 ;
    END
  END WW4END[15]
  PIN WW4END[1]
    DIRECTION INPUT ;
    USE SIGNAL ;
    ANTENNAGATEAREA 0.878700 ;
    ANTENNADIFFAREA 0.434700 ;
    PORT
      LAYER met3 ;
        RECT 171.440 70.760 172.040 71.360 ;
    END
  END WW4END[1]
  PIN WW4END[2]
    DIRECTION INPUT ;
    USE SIGNAL ;
    ANTENNAGATEAREA 1.472400 ;
    ANTENNADIFFAREA 0.869400 ;
    PORT
      LAYER met3 ;
        RECT 171.440 72.120 172.040 72.720 ;
    END
  END WW4END[2]
  PIN WW4END[3]
    DIRECTION INPUT ;
    USE SIGNAL ;
    ANTENNAGATEAREA 2.617500 ;
    ANTENNADIFFAREA 2.173500 ;
    PORT
      LAYER met3 ;
        RECT 171.440 73.480 172.040 74.080 ;
    END
  END WW4END[3]
  PIN WW4END[4]
    DIRECTION INPUT ;
    USE SIGNAL ;
    ANTENNAGATEAREA 0.213000 ;
    PORT
      LAYER met3 ;
        RECT 171.440 74.840 172.040 75.440 ;
    END
  END WW4END[4]
  PIN WW4END[5]
    DIRECTION INPUT ;
    USE SIGNAL ;
    ANTENNAGATEAREA 0.213000 ;
    PORT
      LAYER met3 ;
        RECT 171.440 76.200 172.040 76.800 ;
    END
  END WW4END[5]
  PIN WW4END[6]
    DIRECTION INPUT ;
    USE SIGNAL ;
    ANTENNAGATEAREA 0.213000 ;
    PORT
      LAYER met3 ;
        RECT 171.440 77.560 172.040 78.160 ;
    END
  END WW4END[6]
  PIN WW4END[7]
    DIRECTION INPUT ;
    USE SIGNAL ;
    ANTENNAGATEAREA 0.213000 ;
    PORT
      LAYER met3 ;
        RECT 171.440 78.920 172.040 79.520 ;
    END
  END WW4END[7]
  PIN WW4END[8]
    DIRECTION INPUT ;
    USE SIGNAL ;
    ANTENNAGATEAREA 0.213000 ;
    PORT
      LAYER met3 ;
        RECT 171.440 80.280 172.040 80.880 ;
    END
  END WW4END[8]
  PIN WW4END[9]
    DIRECTION INPUT ;
    USE SIGNAL ;
    ANTENNAGATEAREA 0.213000 ;
    PORT
      LAYER met3 ;
        RECT 171.440 81.640 172.040 82.240 ;
    END
  END WW4END[9]
  OBS
      LAYER nwell ;
        RECT 5.330 5.355 166.710 253.150 ;
      LAYER li1 ;
        RECT 5.520 5.355 166.520 253.045 ;
      LAYER met1 ;
        RECT 0.070 0.040 171.970 258.360 ;
      LAYER met2 ;
        RECT 0.090 259.200 27.870 259.480 ;
        RECT 28.710 259.200 28.790 259.480 ;
        RECT 29.630 259.200 29.710 259.480 ;
        RECT 30.550 259.200 30.630 259.480 ;
        RECT 31.470 259.200 31.550 259.480 ;
        RECT 32.390 259.200 32.470 259.480 ;
        RECT 33.310 259.200 33.390 259.480 ;
        RECT 34.230 259.200 34.310 259.480 ;
        RECT 35.150 259.200 35.230 259.480 ;
        RECT 36.070 259.200 36.150 259.480 ;
        RECT 36.990 259.200 37.070 259.480 ;
        RECT 37.910 259.200 37.990 259.480 ;
        RECT 38.830 259.200 38.910 259.480 ;
        RECT 39.750 259.200 39.830 259.480 ;
        RECT 40.670 259.200 40.750 259.480 ;
        RECT 41.590 259.200 41.670 259.480 ;
        RECT 42.510 259.200 42.590 259.480 ;
        RECT 43.430 259.200 43.510 259.480 ;
        RECT 44.350 259.200 44.430 259.480 ;
        RECT 45.270 259.200 45.350 259.480 ;
        RECT 46.190 259.200 46.270 259.480 ;
        RECT 47.110 259.200 47.190 259.480 ;
        RECT 48.030 259.200 48.110 259.480 ;
        RECT 48.950 259.200 49.030 259.480 ;
        RECT 49.870 259.200 49.950 259.480 ;
        RECT 50.790 259.200 50.870 259.480 ;
        RECT 51.710 259.200 51.790 259.480 ;
        RECT 52.630 259.200 52.710 259.480 ;
        RECT 53.550 259.200 53.630 259.480 ;
        RECT 54.470 259.200 54.550 259.480 ;
        RECT 55.390 259.200 55.470 259.480 ;
        RECT 56.310 259.200 56.390 259.480 ;
        RECT 57.230 259.200 57.310 259.480 ;
        RECT 58.150 259.200 58.230 259.480 ;
        RECT 59.070 259.200 59.150 259.480 ;
        RECT 59.990 259.200 60.070 259.480 ;
        RECT 60.910 259.200 60.990 259.480 ;
        RECT 61.830 259.200 61.910 259.480 ;
        RECT 62.750 259.200 62.830 259.480 ;
        RECT 63.670 259.200 63.750 259.480 ;
        RECT 64.590 259.200 64.670 259.480 ;
        RECT 65.510 259.200 65.590 259.480 ;
        RECT 66.430 259.200 66.510 259.480 ;
        RECT 67.350 259.200 67.430 259.480 ;
        RECT 68.270 259.200 68.350 259.480 ;
        RECT 69.190 259.200 69.270 259.480 ;
        RECT 70.110 259.200 70.190 259.480 ;
        RECT 71.030 259.200 71.110 259.480 ;
        RECT 71.950 259.200 72.030 259.480 ;
        RECT 72.870 259.200 72.950 259.480 ;
        RECT 73.790 259.200 73.870 259.480 ;
        RECT 74.710 259.200 74.790 259.480 ;
        RECT 75.630 259.200 75.710 259.480 ;
        RECT 76.550 259.200 76.630 259.480 ;
        RECT 77.470 259.200 77.550 259.480 ;
        RECT 78.390 259.200 78.470 259.480 ;
        RECT 79.310 259.200 79.390 259.480 ;
        RECT 80.230 259.200 80.310 259.480 ;
        RECT 81.150 259.200 81.230 259.480 ;
        RECT 82.070 259.200 82.150 259.480 ;
        RECT 82.990 259.200 83.070 259.480 ;
        RECT 83.910 259.200 83.990 259.480 ;
        RECT 84.830 259.200 84.910 259.480 ;
        RECT 85.750 259.200 85.830 259.480 ;
        RECT 86.670 259.200 86.750 259.480 ;
        RECT 87.590 259.200 87.670 259.480 ;
        RECT 88.510 259.200 88.590 259.480 ;
        RECT 89.430 259.200 89.510 259.480 ;
        RECT 90.350 259.200 90.430 259.480 ;
        RECT 91.270 259.200 91.350 259.480 ;
        RECT 92.190 259.200 92.270 259.480 ;
        RECT 93.110 259.200 93.190 259.480 ;
        RECT 94.030 259.200 94.110 259.480 ;
        RECT 94.950 259.200 95.030 259.480 ;
        RECT 95.870 259.200 95.950 259.480 ;
        RECT 96.790 259.200 96.870 259.480 ;
        RECT 97.710 259.200 97.790 259.480 ;
        RECT 98.630 259.200 98.710 259.480 ;
        RECT 99.550 259.200 99.630 259.480 ;
        RECT 100.470 259.200 100.550 259.480 ;
        RECT 101.390 259.200 101.470 259.480 ;
        RECT 102.310 259.200 102.390 259.480 ;
        RECT 103.230 259.200 103.310 259.480 ;
        RECT 104.150 259.200 104.230 259.480 ;
        RECT 105.070 259.200 105.150 259.480 ;
        RECT 105.990 259.200 106.070 259.480 ;
        RECT 106.910 259.200 106.990 259.480 ;
        RECT 107.830 259.200 107.910 259.480 ;
        RECT 108.750 259.200 108.830 259.480 ;
        RECT 109.670 259.200 109.750 259.480 ;
        RECT 110.590 259.200 110.670 259.480 ;
        RECT 111.510 259.200 111.590 259.480 ;
        RECT 112.430 259.200 112.510 259.480 ;
        RECT 113.350 259.200 113.430 259.480 ;
        RECT 114.270 259.200 114.350 259.480 ;
        RECT 115.190 259.200 115.270 259.480 ;
        RECT 116.110 259.200 116.190 259.480 ;
        RECT 117.030 259.200 117.110 259.480 ;
        RECT 117.950 259.200 118.030 259.480 ;
        RECT 118.870 259.200 118.950 259.480 ;
        RECT 119.790 259.200 119.870 259.480 ;
        RECT 120.710 259.200 120.790 259.480 ;
        RECT 121.630 259.200 121.710 259.480 ;
        RECT 122.550 259.200 122.630 259.480 ;
        RECT 123.470 259.200 123.550 259.480 ;
        RECT 124.390 259.200 124.470 259.480 ;
        RECT 125.310 259.200 125.390 259.480 ;
        RECT 126.230 259.200 126.310 259.480 ;
        RECT 127.150 259.200 127.230 259.480 ;
        RECT 128.070 259.200 128.150 259.480 ;
        RECT 128.990 259.200 129.070 259.480 ;
        RECT 129.910 259.200 129.990 259.480 ;
        RECT 130.830 259.200 130.910 259.480 ;
        RECT 131.750 259.200 131.830 259.480 ;
        RECT 132.670 259.200 132.750 259.480 ;
        RECT 133.590 259.200 133.670 259.480 ;
        RECT 134.510 259.200 134.590 259.480 ;
        RECT 135.430 259.200 135.510 259.480 ;
        RECT 136.350 259.200 136.430 259.480 ;
        RECT 137.270 259.200 137.350 259.480 ;
        RECT 138.190 259.200 138.270 259.480 ;
        RECT 139.110 259.200 139.190 259.480 ;
        RECT 140.030 259.200 140.110 259.480 ;
        RECT 140.950 259.200 141.030 259.480 ;
        RECT 141.870 259.200 141.950 259.480 ;
        RECT 142.790 259.200 142.870 259.480 ;
        RECT 143.710 259.200 171.940 259.480 ;
        RECT 0.090 0.560 171.940 259.200 ;
        RECT 0.090 0.010 27.870 0.560 ;
        RECT 28.710 0.010 28.790 0.560 ;
        RECT 29.630 0.010 29.710 0.560 ;
        RECT 30.550 0.010 30.630 0.560 ;
        RECT 31.470 0.010 31.550 0.560 ;
        RECT 32.390 0.010 32.470 0.560 ;
        RECT 33.310 0.010 33.390 0.560 ;
        RECT 34.230 0.010 34.310 0.560 ;
        RECT 35.150 0.010 35.230 0.560 ;
        RECT 36.070 0.010 36.150 0.560 ;
        RECT 36.990 0.010 37.070 0.560 ;
        RECT 37.910 0.010 37.990 0.560 ;
        RECT 38.830 0.010 38.910 0.560 ;
        RECT 39.750 0.010 39.830 0.560 ;
        RECT 40.670 0.010 40.750 0.560 ;
        RECT 41.590 0.010 41.670 0.560 ;
        RECT 42.510 0.010 42.590 0.560 ;
        RECT 43.430 0.010 43.510 0.560 ;
        RECT 44.350 0.010 44.430 0.560 ;
        RECT 45.270 0.010 45.350 0.560 ;
        RECT 46.190 0.010 46.270 0.560 ;
        RECT 47.110 0.010 47.190 0.560 ;
        RECT 48.030 0.010 48.110 0.560 ;
        RECT 48.950 0.010 49.030 0.560 ;
        RECT 49.870 0.010 49.950 0.560 ;
        RECT 50.790 0.010 50.870 0.560 ;
        RECT 51.710 0.010 51.790 0.560 ;
        RECT 52.630 0.010 52.710 0.560 ;
        RECT 53.550 0.010 53.630 0.560 ;
        RECT 54.470 0.010 54.550 0.560 ;
        RECT 55.390 0.010 55.470 0.560 ;
        RECT 56.310 0.010 56.390 0.560 ;
        RECT 57.230 0.010 57.310 0.560 ;
        RECT 58.150 0.010 58.230 0.560 ;
        RECT 59.070 0.010 59.150 0.560 ;
        RECT 59.990 0.010 60.070 0.560 ;
        RECT 60.910 0.010 60.990 0.560 ;
        RECT 61.830 0.010 61.910 0.560 ;
        RECT 62.750 0.010 62.830 0.560 ;
        RECT 63.670 0.010 63.750 0.560 ;
        RECT 64.590 0.010 64.670 0.560 ;
        RECT 65.510 0.010 65.590 0.560 ;
        RECT 66.430 0.010 66.510 0.560 ;
        RECT 67.350 0.010 67.430 0.560 ;
        RECT 68.270 0.010 68.350 0.560 ;
        RECT 69.190 0.010 69.270 0.560 ;
        RECT 70.110 0.010 70.190 0.560 ;
        RECT 71.030 0.010 71.110 0.560 ;
        RECT 71.950 0.010 72.030 0.560 ;
        RECT 72.870 0.010 72.950 0.560 ;
        RECT 73.790 0.010 73.870 0.560 ;
        RECT 74.710 0.010 74.790 0.560 ;
        RECT 75.630 0.010 75.710 0.560 ;
        RECT 76.550 0.010 76.630 0.560 ;
        RECT 77.470 0.010 77.550 0.560 ;
        RECT 78.390 0.010 78.470 0.560 ;
        RECT 79.310 0.010 79.390 0.560 ;
        RECT 80.230 0.010 80.310 0.560 ;
        RECT 81.150 0.010 81.230 0.560 ;
        RECT 82.070 0.010 82.150 0.560 ;
        RECT 82.990 0.010 83.070 0.560 ;
        RECT 83.910 0.010 83.990 0.560 ;
        RECT 84.830 0.010 84.910 0.560 ;
        RECT 85.750 0.010 85.830 0.560 ;
        RECT 86.670 0.010 86.750 0.560 ;
        RECT 87.590 0.010 87.670 0.560 ;
        RECT 88.510 0.010 88.590 0.560 ;
        RECT 89.430 0.010 89.510 0.560 ;
        RECT 90.350 0.010 90.430 0.560 ;
        RECT 91.270 0.010 91.350 0.560 ;
        RECT 92.190 0.010 92.270 0.560 ;
        RECT 93.110 0.010 93.190 0.560 ;
        RECT 94.030 0.010 94.110 0.560 ;
        RECT 94.950 0.010 95.030 0.560 ;
        RECT 95.870 0.010 95.950 0.560 ;
        RECT 96.790 0.010 96.870 0.560 ;
        RECT 97.710 0.010 97.790 0.560 ;
        RECT 98.630 0.010 98.710 0.560 ;
        RECT 99.550 0.010 99.630 0.560 ;
        RECT 100.470 0.010 100.550 0.560 ;
        RECT 101.390 0.010 101.470 0.560 ;
        RECT 102.310 0.010 102.390 0.560 ;
        RECT 103.230 0.010 103.310 0.560 ;
        RECT 104.150 0.010 104.230 0.560 ;
        RECT 105.070 0.010 105.150 0.560 ;
        RECT 105.990 0.010 106.070 0.560 ;
        RECT 106.910 0.010 106.990 0.560 ;
        RECT 107.830 0.010 107.910 0.560 ;
        RECT 108.750 0.010 108.830 0.560 ;
        RECT 109.670 0.010 109.750 0.560 ;
        RECT 110.590 0.010 110.670 0.560 ;
        RECT 111.510 0.010 111.590 0.560 ;
        RECT 112.430 0.010 112.510 0.560 ;
        RECT 113.350 0.010 113.430 0.560 ;
        RECT 114.270 0.010 114.350 0.560 ;
        RECT 115.190 0.010 115.270 0.560 ;
        RECT 116.110 0.010 116.190 0.560 ;
        RECT 117.030 0.010 117.110 0.560 ;
        RECT 117.950 0.010 118.030 0.560 ;
        RECT 118.870 0.010 118.950 0.560 ;
        RECT 119.790 0.010 119.870 0.560 ;
        RECT 120.710 0.010 120.790 0.560 ;
        RECT 121.630 0.010 121.710 0.560 ;
        RECT 122.550 0.010 122.630 0.560 ;
        RECT 123.470 0.010 123.550 0.560 ;
        RECT 124.390 0.010 124.470 0.560 ;
        RECT 125.310 0.010 125.390 0.560 ;
        RECT 126.230 0.010 126.310 0.560 ;
        RECT 127.150 0.010 127.230 0.560 ;
        RECT 128.070 0.010 128.150 0.560 ;
        RECT 128.990 0.010 129.070 0.560 ;
        RECT 129.910 0.010 129.990 0.560 ;
        RECT 130.830 0.010 130.910 0.560 ;
        RECT 131.750 0.010 131.830 0.560 ;
        RECT 132.670 0.010 132.750 0.560 ;
        RECT 133.590 0.010 133.670 0.560 ;
        RECT 134.510 0.010 134.590 0.560 ;
        RECT 135.430 0.010 135.510 0.560 ;
        RECT 136.350 0.010 136.430 0.560 ;
        RECT 137.270 0.010 137.350 0.560 ;
        RECT 138.190 0.010 138.270 0.560 ;
        RECT 139.110 0.010 139.190 0.560 ;
        RECT 140.030 0.010 140.110 0.560 ;
        RECT 140.950 0.010 141.030 0.560 ;
        RECT 141.870 0.010 141.950 0.560 ;
        RECT 142.790 0.010 142.870 0.560 ;
        RECT 143.710 0.010 171.940 0.560 ;
      LAYER met3 ;
        RECT 0.065 215.920 171.770 259.585 ;
        RECT 1.000 41.800 171.040 215.920 ;
        RECT 0.065 0.175 171.770 41.800 ;
      LAYER met4 ;
        RECT 0.150 0.175 9.320 259.585 ;
        RECT 11.720 0.175 14.620 259.585 ;
        RECT 17.020 0.175 39.320 259.585 ;
        RECT 41.720 0.175 44.620 259.585 ;
        RECT 47.020 0.175 69.320 259.585 ;
        RECT 71.720 0.175 74.620 259.585 ;
        RECT 77.020 0.175 99.320 259.585 ;
        RECT 101.720 0.175 104.620 259.585 ;
        RECT 107.020 0.175 129.320 259.585 ;
        RECT 131.720 0.175 134.620 259.585 ;
        RECT 137.020 0.175 159.320 259.585 ;
        RECT 161.720 0.175 164.620 259.585 ;
        RECT 167.020 0.175 171.745 259.585 ;
  END
END SimpleCLB
END LIBRARY

